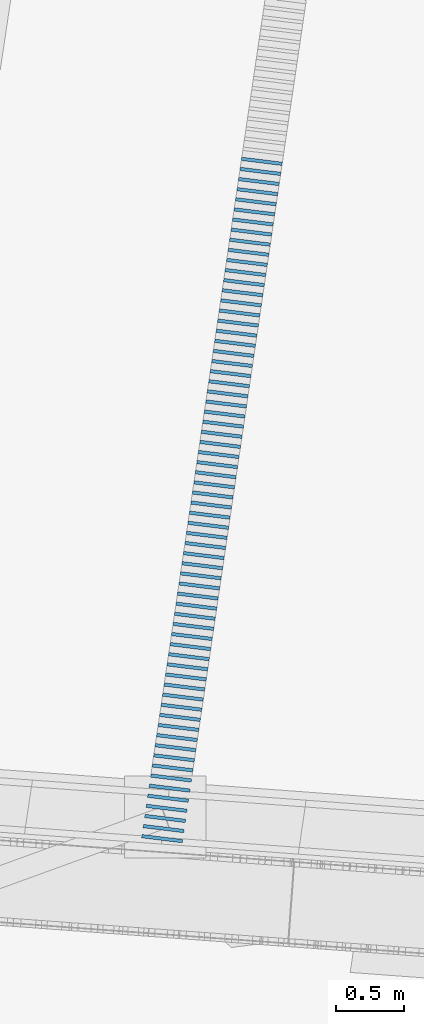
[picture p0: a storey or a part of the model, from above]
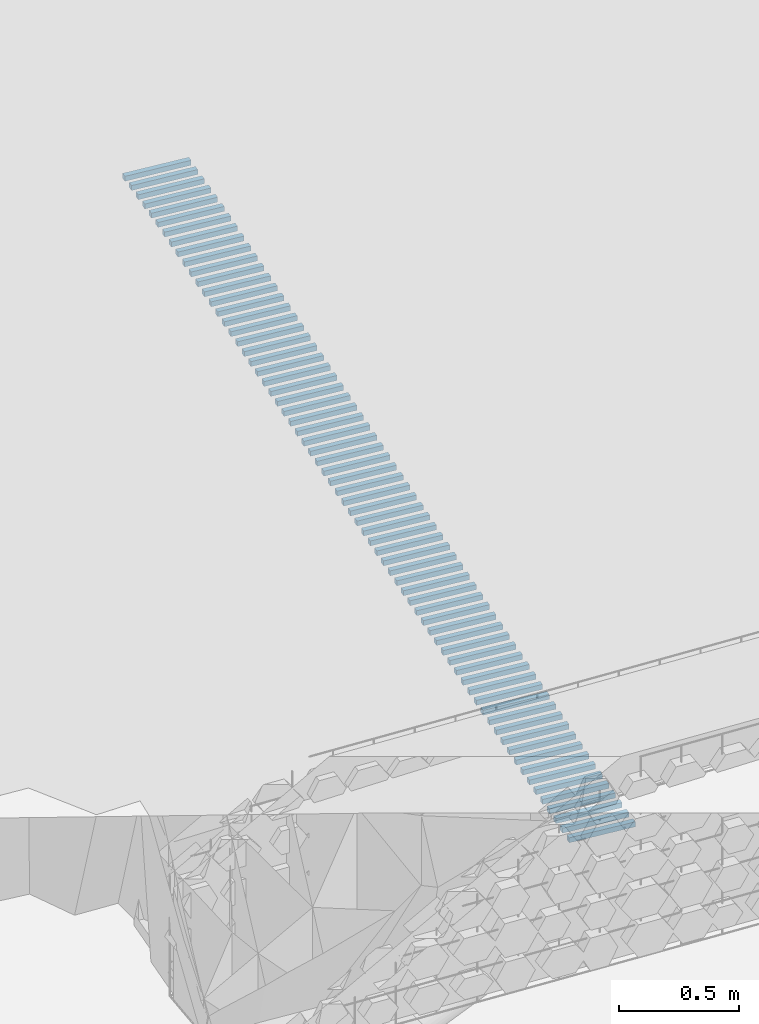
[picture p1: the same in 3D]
Properties of the parts of a building model (IFC4), part 1 of 3

# File
Description: ViewDefinition [CoordinationView]
File name: Casa_Sobreposta_Implantada.ifc
Time: 2026-10-02T12:27:42
Written by: IfcOpenShell 0.8.0
Made in: IfcOpenShell 0.8.0

# IfcProject, Casa Sobreposta · Lares · R06
Pset_CasaModel - Design: R06 single-storey exposed timber tiled roof, no attic floor; ReferenceFile: 260617_CasaDFL_Estrutura_Terreno.ifc; ModelStatus: DESIGN_STUDY; North: Survey grid +Y; Ramp: No upper floor or pedestrian ramp; EngineeringStatus: Member sizes, foundations, connections, bracing and environmental performance not verified; GroundFFL_m: 13.9; AreaLimit_m2: 250; CountedGeometricArea_m2: 163.712; GreenhouseExcludedByUser: no

# IfcSite, Lares · Rua das Mercês · artigo 4771
Pset_SurveySource - File: GN_09.26_213 Lares.dwg; SHA256: 0bca0a0751148bad1398f92d81b795428f94a57fea5e37dec0e125cea70402a1; Area_m2: 1636.5; BoundaryHandle: 31B; CoordinateReference: PT-TM06 / ETRS89; TerrainStatus: Proposed grading; original survey in separate IFC

# IfcBuilding, Casa Sobreposta
Pset_CasaPlacement - GroundFloorSurveyLevel_m: 13.9; UpperFloor: no; MoveEast_m: 3; MoveSouth_m: 0.5; RotationFromGridEast_deg: -8.5; BoundarySetbackRequired_m: 3; RuleBasis: User project constraint

# IfcBuildingStorey (2)
In: Casa Sobreposta
Name | Elevation (m)
00 · Habitação e estacionamento | 13.9
-01 · Cisterna sob o terraço | 11.3

# IfcSpace (11)
In: 00 · Habitação e estacionamento
Pset_CasaProvenance - DesignSource: Casa Sobreposta / configuration.json; ReferenceFile: 260617_CasaDFL_Estrutura_Terreno.ifc; ConstructionBasis: DESIGN_ASSUMPTION; Note: Functional zone from configurator; overlaps with partition footprints removed on ground floor. Not certified usable floor area.
Name | PredefinedType | NetFloorArea (m2)
Sala | INTERNAL | 31.359
Cozinha | INTERNAL | 9.94248
Banho | INTERNAL | 7.19804
WC | INTERNAL | 1.231
Serviço | INTERNAL | 4.16058
Acesso IS | INTERNAL | 3.99017
Quarto 1 | INTERNAL | 13.1145
Quarto 2 | INTERNAL | 13.1145
Quarto / escritório | INTERNAL | 37.8909
Circulação | INTERNAL | 18.1139
Estacionamento · 2 lugares | EXTERNAL | 32.55

# IfcAnnotation (4)
Pset_CasaProvenance - DesignSource: Casa Sobreposta / configuration.json; ReferenceFile: 260617_CasaDFL_Estrutura_Terreno.ifc; ConstructionBasis: DESIGN_ASSUMPTION
Name | In
Lugar P1 · 2.50 x 5.00 m | 00 · Habitação e estacionamento
Lugar P2 · 2.50 x 5.00 m | 00 · Habitação e estacionamento
Limite levantado · 31B | Lares · Rua das Mercês · artigo 4771
Afastamento de implantação · 3 m | Lares · Rua das Mercês · artigo 4771

# IfcBeam: TIMBER0.140x0.220 / timber (5)
In: 00 · Habitação e estacionamento
Type - Material: Madeira / Bauholz
Pset_CasaProvenance - DesignSource: Casa Sobreposta / configuration.json; ReferenceFile: 260617_CasaDFL_Estrutura_Terreno.ifc; ConstructionBasis: DESIGN_ASSUMPTION; Note: Visible timber concept; strength class, deflection, stability, wind and fire design pending.

# IfcBeam: TIMBER0.160x0.220 / timber (2)
In: 00 · Habitação e estacionamento
Type - Material: Madeira / Bauholz
Pset_CasaProvenance - DesignSource: Casa Sobreposta / configuration.json; ReferenceFile: 260617_CasaDFL_Estrutura_Terreno.ifc; ConstructionBasis: DESIGN_ASSUMPTION; Note: Visible timber concept; strength class, deflection, stability, wind and fire design pending.

# IfcBeam: TIMBER0.160x0.240 / timber (11)
In: 00 · Habitação e estacionamento
Type - Material: Madeira / Bauholz
Pset_CasaProvenance - DesignSource: Casa Sobreposta / configuration.json; ReferenceFile: 260617_CasaDFL_Estrutura_Terreno.ifc; ConstructionBasis: DESIGN_ASSUMPTION; Note: Visible timber concept; strength class, deflection, stability, wind and fire design pending.
Name
9 x Tesoura · tirante inferior
2 x Pérgola · viga

# IfcBuildingElementProxy: Acesso · caixa de retenção de sedimentos (2)
In: Lares · Rua das Mercês · artigo 4771
PredefinedType: USERDEFINED; Material: Caleiras · betão
Pset_CasaProvenance - DesignSource: Casa Sobreposta / configuration.json; ReferenceFile: 260617_CasaDFL_Estrutura_Terreno.ifc; ConstructionBasis: DESIGN_ASSUMPTION

# IfcBuildingElementProxy: Acesso · canal lateral (222)
In: Lares · Rua das Mercês · artigo 4771
PredefinedType: USERDEFINED; Material: Caleiras · betão
Pset_CasaProvenance - DesignSource: Casa Sobreposta / configuration.json; ReferenceFile: 260617_CasaDFL_Estrutura_Terreno.ifc; ConstructionBasis: DESIGN_ASSUMPTION; Note: R06 concept geometry; dimensions and connections not structurally verified.

# IfcBuildingElementProxy: Acesso · gabião -1 0.0 · cesto galvanizado
In: Lares · Rua das Mercês · artigo 4771
PredefinedType: USERDEFINED; Material: Aço galvanizado / Stahl verzinkt
Pset_CasaProvenance - DesignSource: Casa Sobreposta / configuration.json; ReferenceFile: 260617_CasaDFL_Estrutura_Terreno.ifc; ConstructionBasis: DESIGN_ASSUMPTION; Note: R06 concept geometry; dimensions and connections not structurally verified.

# IfcBuildingElementProxy: Acesso · gabião -1 0.0 · pedra aparente
In: Lares · Rua das Mercês · artigo 4771
PredefinedType: USERDEFINED; Material: Gabião · pedra irregular
Pset_CasaProvenance - DesignSource: Casa Sobreposta / configuration.json; ReferenceFile: 260617_CasaDFL_Estrutura_Terreno.ifc; ConstructionBasis: DESIGN_ASSUMPTION; Note: R06 concept geometry; dimensions and connections not structurally verified.

# IfcBuildingElementProxy: Acesso · gabião -1 12.0 · cesto galvanizado
In: Lares · Rua das Mercês · artigo 4771
PredefinedType: USERDEFINED; Material: Aço galvanizado / Stahl verzinkt
Pset_CasaProvenance - DesignSource: Casa Sobreposta / configuration.json; ReferenceFile: 260617_CasaDFL_Estrutura_Terreno.ifc; ConstructionBasis: DESIGN_ASSUMPTION; Note: R06 concept geometry; dimensions and connections not structurally verified.

# IfcBuildingElementProxy: Acesso · gabião -1 12.0 · pedra aparente
In: Lares · Rua das Mercês · artigo 4771
PredefinedType: USERDEFINED; Material: Gabião · pedra irregular
Pset_CasaProvenance - DesignSource: Casa Sobreposta / configuration.json; ReferenceFile: 260617_CasaDFL_Estrutura_Terreno.ifc; ConstructionBasis: DESIGN_ASSUMPTION; Note: R06 concept geometry; dimensions and connections not structurally verified.

# IfcBuildingElementProxy: Acesso · gabião -1 15.0 · cesto galvanizado
In: Lares · Rua das Mercês · artigo 4771
PredefinedType: USERDEFINED; Material: Aço galvanizado / Stahl verzinkt
Pset_CasaProvenance - DesignSource: Casa Sobreposta / configuration.json; ReferenceFile: 260617_CasaDFL_Estrutura_Terreno.ifc; ConstructionBasis: DESIGN_ASSUMPTION; Note: R06 concept geometry; dimensions and connections not structurally verified.

# IfcBuildingElementProxy: Acesso · gabião -1 15.0 · pedra aparente
In: Lares · Rua das Mercês · artigo 4771
PredefinedType: USERDEFINED; Material: Gabião · pedra irregular
Pset_CasaProvenance - DesignSource: Casa Sobreposta / configuration.json; ReferenceFile: 260617_CasaDFL_Estrutura_Terreno.ifc; ConstructionBasis: DESIGN_ASSUMPTION; Note: R06 concept geometry; dimensions and connections not structurally verified.

# IfcBuildingElementProxy: Acesso · gabião -1 18.0 · cesto galvanizado
In: Lares · Rua das Mercês · artigo 4771
PredefinedType: USERDEFINED; Material: Aço galvanizado / Stahl verzinkt
Pset_CasaProvenance - DesignSource: Casa Sobreposta / configuration.json; ReferenceFile: 260617_CasaDFL_Estrutura_Terreno.ifc; ConstructionBasis: DESIGN_ASSUMPTION; Note: R06 concept geometry; dimensions and connections not structurally verified.

# IfcBuildingElementProxy: Acesso · gabião -1 18.0 · pedra aparente
In: Lares · Rua das Mercês · artigo 4771
PredefinedType: USERDEFINED; Material: Gabião · pedra irregular
Pset_CasaProvenance - DesignSource: Casa Sobreposta / configuration.json; ReferenceFile: 260617_CasaDFL_Estrutura_Terreno.ifc; ConstructionBasis: DESIGN_ASSUMPTION; Note: R06 concept geometry; dimensions and connections not structurally verified.

# IfcBuildingElementProxy: Acesso · gabião -1 21.0 · cesto galvanizado
In: Lares · Rua das Mercês · artigo 4771
PredefinedType: USERDEFINED; Material: Aço galvanizado / Stahl verzinkt
Pset_CasaProvenance - DesignSource: Casa Sobreposta / configuration.json; ReferenceFile: 260617_CasaDFL_Estrutura_Terreno.ifc; ConstructionBasis: DESIGN_ASSUMPTION; Note: R06 concept geometry; dimensions and connections not structurally verified.

# IfcBuildingElementProxy: Acesso · gabião -1 21.0 · pedra aparente
In: Lares · Rua das Mercês · artigo 4771
PredefinedType: USERDEFINED; Material: Gabião · pedra irregular
Pset_CasaProvenance - DesignSource: Casa Sobreposta / configuration.json; ReferenceFile: 260617_CasaDFL_Estrutura_Terreno.ifc; ConstructionBasis: DESIGN_ASSUMPTION; Note: R06 concept geometry; dimensions and connections not structurally verified.

# IfcBuildingElementProxy: Acesso · gabião -1 24.0 · cesto galvanizado
In: Lares · Rua das Mercês · artigo 4771
PredefinedType: USERDEFINED; Material: Aço galvanizado / Stahl verzinkt
Pset_CasaProvenance - DesignSource: Casa Sobreposta / configuration.json; ReferenceFile: 260617_CasaDFL_Estrutura_Terreno.ifc; ConstructionBasis: DESIGN_ASSUMPTION; Note: R06 concept geometry; dimensions and connections not structurally verified.

# IfcBuildingElementProxy: Acesso · gabião -1 24.0 · pedra aparente
In: Lares · Rua das Mercês · artigo 4771
PredefinedType: USERDEFINED; Material: Gabião · pedra irregular
Pset_CasaProvenance - DesignSource: Casa Sobreposta / configuration.json; ReferenceFile: 260617_CasaDFL_Estrutura_Terreno.ifc; ConstructionBasis: DESIGN_ASSUMPTION; Note: R06 concept geometry; dimensions and connections not structurally verified.

# IfcBuildingElementProxy: Acesso · gabião -1 27.0 · cesto galvanizado
In: Lares · Rua das Mercês · artigo 4771
PredefinedType: USERDEFINED; Material: Aço galvanizado / Stahl verzinkt
Pset_CasaProvenance - DesignSource: Casa Sobreposta / configuration.json; ReferenceFile: 260617_CasaDFL_Estrutura_Terreno.ifc; ConstructionBasis: DESIGN_ASSUMPTION; Note: R06 concept geometry; dimensions and connections not structurally verified.

# IfcBuildingElementProxy: Acesso · gabião -1 27.0 · pedra aparente
In: Lares · Rua das Mercês · artigo 4771
PredefinedType: USERDEFINED; Material: Gabião · pedra irregular
Pset_CasaProvenance - DesignSource: Casa Sobreposta / configuration.json; ReferenceFile: 260617_CasaDFL_Estrutura_Terreno.ifc; ConstructionBasis: DESIGN_ASSUMPTION; Note: R06 concept geometry; dimensions and connections not structurally verified.

# IfcBuildingElementProxy: Acesso · gabião -1 3.0 · cesto galvanizado
In: Lares · Rua das Mercês · artigo 4771
PredefinedType: USERDEFINED; Material: Aço galvanizado / Stahl verzinkt
Pset_CasaProvenance - DesignSource: Casa Sobreposta / configuration.json; ReferenceFile: 260617_CasaDFL_Estrutura_Terreno.ifc; ConstructionBasis: DESIGN_ASSUMPTION; Note: R06 concept geometry; dimensions and connections not structurally verified.

# IfcBuildingElementProxy: Acesso · gabião -1 3.0 · pedra aparente
In: Lares · Rua das Mercês · artigo 4771
PredefinedType: USERDEFINED; Material: Gabião · pedra irregular
Pset_CasaProvenance - DesignSource: Casa Sobreposta / configuration.json; ReferenceFile: 260617_CasaDFL_Estrutura_Terreno.ifc; ConstructionBasis: DESIGN_ASSUMPTION; Note: R06 concept geometry; dimensions and connections not structurally verified.

# IfcBuildingElementProxy: Acesso · gabião -1 30.0 · cesto galvanizado
In: Lares · Rua das Mercês · artigo 4771
PredefinedType: USERDEFINED; Material: Aço galvanizado / Stahl verzinkt
Pset_CasaProvenance - DesignSource: Casa Sobreposta / configuration.json; ReferenceFile: 260617_CasaDFL_Estrutura_Terreno.ifc; ConstructionBasis: DESIGN_ASSUMPTION; Note: R06 concept geometry; dimensions and connections not structurally verified.

# IfcBuildingElementProxy: Acesso · gabião -1 30.0 · pedra aparente
In: Lares · Rua das Mercês · artigo 4771
PredefinedType: USERDEFINED; Material: Gabião · pedra irregular
Pset_CasaProvenance - DesignSource: Casa Sobreposta / configuration.json; ReferenceFile: 260617_CasaDFL_Estrutura_Terreno.ifc; ConstructionBasis: DESIGN_ASSUMPTION; Note: R06 concept geometry; dimensions and connections not structurally verified.

# IfcBuildingElementProxy: Acesso · gabião -1 33.0 · cesto galvanizado
In: Lares · Rua das Mercês · artigo 4771
PredefinedType: USERDEFINED; Material: Aço galvanizado / Stahl verzinkt
Pset_CasaProvenance - DesignSource: Casa Sobreposta / configuration.json; ReferenceFile: 260617_CasaDFL_Estrutura_Terreno.ifc; ConstructionBasis: DESIGN_ASSUMPTION; Note: R06 concept geometry; dimensions and connections not structurally verified.

# IfcBuildingElementProxy: Acesso · gabião -1 33.0 · pedra aparente
In: Lares · Rua das Mercês · artigo 4771
PredefinedType: USERDEFINED; Material: Gabião · pedra irregular
Pset_CasaProvenance - DesignSource: Casa Sobreposta / configuration.json; ReferenceFile: 260617_CasaDFL_Estrutura_Terreno.ifc; ConstructionBasis: DESIGN_ASSUMPTION; Note: R06 concept geometry; dimensions and connections not structurally verified.

# IfcBuildingElementProxy: Acesso · gabião -1 6.0 · cesto galvanizado
In: Lares · Rua das Mercês · artigo 4771
PredefinedType: USERDEFINED; Material: Aço galvanizado / Stahl verzinkt
Pset_CasaProvenance - DesignSource: Casa Sobreposta / configuration.json; ReferenceFile: 260617_CasaDFL_Estrutura_Terreno.ifc; ConstructionBasis: DESIGN_ASSUMPTION; Note: R06 concept geometry; dimensions and connections not structurally verified.

# IfcBuildingElementProxy: Acesso · gabião -1 6.0 · pedra aparente
In: Lares · Rua das Mercês · artigo 4771
PredefinedType: USERDEFINED; Material: Gabião · pedra irregular
Pset_CasaProvenance - DesignSource: Casa Sobreposta / configuration.json; ReferenceFile: 260617_CasaDFL_Estrutura_Terreno.ifc; ConstructionBasis: DESIGN_ASSUMPTION; Note: R06 concept geometry; dimensions and connections not structurally verified.

# IfcBuildingElementProxy: Acesso · gabião -1 9.0 · cesto galvanizado
In: Lares · Rua das Mercês · artigo 4771
PredefinedType: USERDEFINED; Material: Aço galvanizado / Stahl verzinkt
Pset_CasaProvenance - DesignSource: Casa Sobreposta / configuration.json; ReferenceFile: 260617_CasaDFL_Estrutura_Terreno.ifc; ConstructionBasis: DESIGN_ASSUMPTION; Note: R06 concept geometry; dimensions and connections not structurally verified.

# IfcBuildingElementProxy: Acesso · gabião -1 9.0 · pedra aparente
In: Lares · Rua das Mercês · artigo 4771
PredefinedType: USERDEFINED; Material: Gabião · pedra irregular
Pset_CasaProvenance - DesignSource: Casa Sobreposta / configuration.json; ReferenceFile: 260617_CasaDFL_Estrutura_Terreno.ifc; ConstructionBasis: DESIGN_ASSUMPTION; Note: R06 concept geometry; dimensions and connections not structurally verified.

# IfcBuildingElementProxy: Acesso · gabião 1 0.0 · cesto galvanizado
In: Lares · Rua das Mercês · artigo 4771
PredefinedType: USERDEFINED; Material: Aço galvanizado / Stahl verzinkt
Pset_CasaProvenance - DesignSource: Casa Sobreposta / configuration.json; ReferenceFile: 260617_CasaDFL_Estrutura_Terreno.ifc; ConstructionBasis: DESIGN_ASSUMPTION; Note: R06 concept geometry; dimensions and connections not structurally verified.

# IfcBuildingElementProxy: Acesso · gabião 1 0.0 · pedra aparente
In: Lares · Rua das Mercês · artigo 4771
PredefinedType: USERDEFINED; Material: Gabião · pedra irregular
Pset_CasaProvenance - DesignSource: Casa Sobreposta / configuration.json; ReferenceFile: 260617_CasaDFL_Estrutura_Terreno.ifc; ConstructionBasis: DESIGN_ASSUMPTION; Note: R06 concept geometry; dimensions and connections not structurally verified.

# IfcBuildingElementProxy: Acesso · gabião 1 12.0 · cesto galvanizado
In: Lares · Rua das Mercês · artigo 4771
PredefinedType: USERDEFINED; Material: Aço galvanizado / Stahl verzinkt
Pset_CasaProvenance - DesignSource: Casa Sobreposta / configuration.json; ReferenceFile: 260617_CasaDFL_Estrutura_Terreno.ifc; ConstructionBasis: DESIGN_ASSUMPTION; Note: R06 concept geometry; dimensions and connections not structurally verified.

# IfcBuildingElementProxy: Acesso · gabião 1 12.0 · pedra aparente
In: Lares · Rua das Mercês · artigo 4771
PredefinedType: USERDEFINED; Material: Gabião · pedra irregular
Pset_CasaProvenance - DesignSource: Casa Sobreposta / configuration.json; ReferenceFile: 260617_CasaDFL_Estrutura_Terreno.ifc; ConstructionBasis: DESIGN_ASSUMPTION; Note: R06 concept geometry; dimensions and connections not structurally verified.

# IfcBuildingElementProxy: Acesso · gabião 1 15.0 · cesto galvanizado
In: Lares · Rua das Mercês · artigo 4771
PredefinedType: USERDEFINED; Material: Aço galvanizado / Stahl verzinkt
Pset_CasaProvenance - DesignSource: Casa Sobreposta / configuration.json; ReferenceFile: 260617_CasaDFL_Estrutura_Terreno.ifc; ConstructionBasis: DESIGN_ASSUMPTION; Note: R06 concept geometry; dimensions and connections not structurally verified.

# IfcBuildingElementProxy: Acesso · gabião 1 15.0 · pedra aparente
In: Lares · Rua das Mercês · artigo 4771
PredefinedType: USERDEFINED; Material: Gabião · pedra irregular
Pset_CasaProvenance - DesignSource: Casa Sobreposta / configuration.json; ReferenceFile: 260617_CasaDFL_Estrutura_Terreno.ifc; ConstructionBasis: DESIGN_ASSUMPTION; Note: R06 concept geometry; dimensions and connections not structurally verified.

# IfcBuildingElementProxy: Acesso · gabião 1 18.0 · cesto galvanizado
In: Lares · Rua das Mercês · artigo 4771
PredefinedType: USERDEFINED; Material: Aço galvanizado / Stahl verzinkt
Pset_CasaProvenance - DesignSource: Casa Sobreposta / configuration.json; ReferenceFile: 260617_CasaDFL_Estrutura_Terreno.ifc; ConstructionBasis: DESIGN_ASSUMPTION; Note: R06 concept geometry; dimensions and connections not structurally verified.

# IfcBuildingElementProxy: Acesso · gabião 1 18.0 · pedra aparente
In: Lares · Rua das Mercês · artigo 4771
PredefinedType: USERDEFINED; Material: Gabião · pedra irregular
Pset_CasaProvenance - DesignSource: Casa Sobreposta / configuration.json; ReferenceFile: 260617_CasaDFL_Estrutura_Terreno.ifc; ConstructionBasis: DESIGN_ASSUMPTION; Note: R06 concept geometry; dimensions and connections not structurally verified.

# IfcBuildingElementProxy: Acesso · gabião 1 21.0 · cesto galvanizado
In: Lares · Rua das Mercês · artigo 4771
PredefinedType: USERDEFINED; Material: Aço galvanizado / Stahl verzinkt
Pset_CasaProvenance - DesignSource: Casa Sobreposta / configuration.json; ReferenceFile: 260617_CasaDFL_Estrutura_Terreno.ifc; ConstructionBasis: DESIGN_ASSUMPTION; Note: R06 concept geometry; dimensions and connections not structurally verified.

# IfcBuildingElementProxy: Acesso · gabião 1 21.0 · pedra aparente
In: Lares · Rua das Mercês · artigo 4771
PredefinedType: USERDEFINED; Material: Gabião · pedra irregular
Pset_CasaProvenance - DesignSource: Casa Sobreposta / configuration.json; ReferenceFile: 260617_CasaDFL_Estrutura_Terreno.ifc; ConstructionBasis: DESIGN_ASSUMPTION; Note: R06 concept geometry; dimensions and connections not structurally verified.

# IfcBuildingElementProxy: Acesso · gabião 1 24.0 · cesto galvanizado
In: Lares · Rua das Mercês · artigo 4771
PredefinedType: USERDEFINED; Material: Aço galvanizado / Stahl verzinkt
Pset_CasaProvenance - DesignSource: Casa Sobreposta / configuration.json; ReferenceFile: 260617_CasaDFL_Estrutura_Terreno.ifc; ConstructionBasis: DESIGN_ASSUMPTION; Note: R06 concept geometry; dimensions and connections not structurally verified.

# IfcBuildingElementProxy: Acesso · gabião 1 24.0 · pedra aparente
In: Lares · Rua das Mercês · artigo 4771
PredefinedType: USERDEFINED; Material: Gabião · pedra irregular
Pset_CasaProvenance - DesignSource: Casa Sobreposta / configuration.json; ReferenceFile: 260617_CasaDFL_Estrutura_Terreno.ifc; ConstructionBasis: DESIGN_ASSUMPTION; Note: R06 concept geometry; dimensions and connections not structurally verified.

# IfcBuildingElementProxy: Acesso · gabião 1 27.0 · cesto galvanizado
In: Lares · Rua das Mercês · artigo 4771
PredefinedType: USERDEFINED; Material: Aço galvanizado / Stahl verzinkt
Pset_CasaProvenance - DesignSource: Casa Sobreposta / configuration.json; ReferenceFile: 260617_CasaDFL_Estrutura_Terreno.ifc; ConstructionBasis: DESIGN_ASSUMPTION; Note: R06 concept geometry; dimensions and connections not structurally verified.

# IfcBuildingElementProxy: Acesso · gabião 1 27.0 · pedra aparente
In: Lares · Rua das Mercês · artigo 4771
PredefinedType: USERDEFINED; Material: Gabião · pedra irregular
Pset_CasaProvenance - DesignSource: Casa Sobreposta / configuration.json; ReferenceFile: 260617_CasaDFL_Estrutura_Terreno.ifc; ConstructionBasis: DESIGN_ASSUMPTION; Note: R06 concept geometry; dimensions and connections not structurally verified.

# IfcBuildingElementProxy: Acesso · gabião 1 3.0 · cesto galvanizado
In: Lares · Rua das Mercês · artigo 4771
PredefinedType: USERDEFINED; Material: Aço galvanizado / Stahl verzinkt
Pset_CasaProvenance - DesignSource: Casa Sobreposta / configuration.json; ReferenceFile: 260617_CasaDFL_Estrutura_Terreno.ifc; ConstructionBasis: DESIGN_ASSUMPTION; Note: R06 concept geometry; dimensions and connections not structurally verified.

# IfcBuildingElementProxy: Acesso · gabião 1 3.0 · pedra aparente
In: Lares · Rua das Mercês · artigo 4771
PredefinedType: USERDEFINED; Material: Gabião · pedra irregular
Pset_CasaProvenance - DesignSource: Casa Sobreposta / configuration.json; ReferenceFile: 260617_CasaDFL_Estrutura_Terreno.ifc; ConstructionBasis: DESIGN_ASSUMPTION; Note: R06 concept geometry; dimensions and connections not structurally verified.

# IfcBuildingElementProxy: Acesso · gabião 1 30.0 · cesto galvanizado
In: Lares · Rua das Mercês · artigo 4771
PredefinedType: USERDEFINED; Material: Aço galvanizado / Stahl verzinkt
Pset_CasaProvenance - DesignSource: Casa Sobreposta / configuration.json; ReferenceFile: 260617_CasaDFL_Estrutura_Terreno.ifc; ConstructionBasis: DESIGN_ASSUMPTION; Note: R06 concept geometry; dimensions and connections not structurally verified.

# IfcBuildingElementProxy: Acesso · gabião 1 30.0 · pedra aparente
In: Lares · Rua das Mercês · artigo 4771
PredefinedType: USERDEFINED; Material: Gabião · pedra irregular
Pset_CasaProvenance - DesignSource: Casa Sobreposta / configuration.json; ReferenceFile: 260617_CasaDFL_Estrutura_Terreno.ifc; ConstructionBasis: DESIGN_ASSUMPTION; Note: R06 concept geometry; dimensions and connections not structurally verified.

# IfcBuildingElementProxy: Acesso · gabião 1 33.0 · cesto galvanizado
In: Lares · Rua das Mercês · artigo 4771
PredefinedType: USERDEFINED; Material: Aço galvanizado / Stahl verzinkt
Pset_CasaProvenance - DesignSource: Casa Sobreposta / configuration.json; ReferenceFile: 260617_CasaDFL_Estrutura_Terreno.ifc; ConstructionBasis: DESIGN_ASSUMPTION; Note: R06 concept geometry; dimensions and connections not structurally verified.

# IfcBuildingElementProxy: Acesso · gabião 1 33.0 · pedra aparente
In: Lares · Rua das Mercês · artigo 4771
PredefinedType: USERDEFINED; Material: Gabião · pedra irregular
Pset_CasaProvenance - DesignSource: Casa Sobreposta / configuration.json; ReferenceFile: 260617_CasaDFL_Estrutura_Terreno.ifc; ConstructionBasis: DESIGN_ASSUMPTION; Note: R06 concept geometry; dimensions and connections not structurally verified.

# IfcBuildingElementProxy: Acesso · gabião 1 6.0 · cesto galvanizado
In: Lares · Rua das Mercês · artigo 4771
PredefinedType: USERDEFINED; Material: Aço galvanizado / Stahl verzinkt
Pset_CasaProvenance - DesignSource: Casa Sobreposta / configuration.json; ReferenceFile: 260617_CasaDFL_Estrutura_Terreno.ifc; ConstructionBasis: DESIGN_ASSUMPTION; Note: R06 concept geometry; dimensions and connections not structurally verified.

# IfcBuildingElementProxy: Acesso · gabião 1 6.0 · pedra aparente
In: Lares · Rua das Mercês · artigo 4771
PredefinedType: USERDEFINED; Material: Gabião · pedra irregular
Pset_CasaProvenance - DesignSource: Casa Sobreposta / configuration.json; ReferenceFile: 260617_CasaDFL_Estrutura_Terreno.ifc; ConstructionBasis: DESIGN_ASSUMPTION; Note: R06 concept geometry; dimensions and connections not structurally verified.

# IfcBuildingElementProxy: Acesso · gabião 1 9.0 · cesto galvanizado
In: Lares · Rua das Mercês · artigo 4771
PredefinedType: USERDEFINED; Material: Aço galvanizado / Stahl verzinkt
Pset_CasaProvenance - DesignSource: Casa Sobreposta / configuration.json; ReferenceFile: 260617_CasaDFL_Estrutura_Terreno.ifc; ConstructionBasis: DESIGN_ASSUMPTION; Note: R06 concept geometry; dimensions and connections not structurally verified.

# IfcBuildingElementProxy: Acesso · gabião 1 9.0 · pedra aparente
In: Lares · Rua das Mercês · artigo 4771
PredefinedType: USERDEFINED; Material: Gabião · pedra irregular
Pset_CasaProvenance - DesignSource: Casa Sobreposta / configuration.json; ReferenceFile: 260617_CasaDFL_Estrutura_Terreno.ifc; ConstructionBasis: DESIGN_ASSUMPTION; Note: R06 concept geometry; dimensions and connections not structurally verified.

# IfcBuildingElementProxy: Cisterna · água a 2,00 m, hipótese
In: -01 · Cisterna sob o terraço
PredefinedType: USERDEFINED; Material: Água pluvial · nível ilustrativo
Pset_CasaProvenance - DesignSource: Casa Sobreposta / configuration.json; ReferenceFile: 260617_CasaDFL_Estrutura_Terreno.ifc; ConstructionBasis: DESIGN_ASSUMPTION; Note: Illustrative water envelope, not concrete or a certified operating capacity.

# IfcBuildingElementProxy: Cobertura · caleira pluvial para cisterna (2)
In: 00 · Habitação e estacionamento
PredefinedType: USERDEFINED; Material: Aço galvanizado / Stahl verzinkt
Pset_CasaProvenance - DesignSource: Casa Sobreposta / configuration.json; ReferenceFile: 260617_CasaDFL_Estrutura_Terreno.ifc; ConstructionBasis: DESIGN_ASSUMPTION

# IfcBuildingElementProxy: Interceção · caleira estacionamento
In: Lares · Rua das Mercês · artigo 4771
PredefinedType: USERDEFINED; Material: Caleiras · betão
Pset_CasaProvenance - DesignSource: Casa Sobreposta / configuration.json; ReferenceFile: 260617_CasaDFL_Estrutura_Terreno.ifc; ConstructionBasis: DESIGN_ASSUMPTION

# IfcBuildingElementProxy: Interceção · caleira rua
In: Lares · Rua das Mercês · artigo 4771
PredefinedType: USERDEFINED; Material: Caleiras · betão
Pset_CasaProvenance - DesignSource: Casa Sobreposta / configuration.json; ReferenceFile: 260617_CasaDFL_Estrutura_Terreno.ifc; ConstructionBasis: DESIGN_ASSUMPTION

# IfcBuildingElementProxy: Limite north · gabião 10 · cesto galvanizado
In: Lares · Rua das Mercês · artigo 4771
PredefinedType: USERDEFINED; Material: Aço galvanizado / Stahl verzinkt
Pset_CasaProvenance - DesignSource: Casa Sobreposta / configuration.json; ReferenceFile: 260617_CasaDFL_Estrutura_Terreno.ifc; ConstructionBasis: DESIGN_ASSUMPTION; Note: R06 concept geometry; dimensions and connections not structurally verified.

# IfcBuildingElementProxy: Limite north · gabião 10 · pedra aparente
In: Lares · Rua das Mercês · artigo 4771
PredefinedType: USERDEFINED; Material: Gabião · pedra irregular
Pset_CasaProvenance - DesignSource: Casa Sobreposta / configuration.json; ReferenceFile: 260617_CasaDFL_Estrutura_Terreno.ifc; ConstructionBasis: DESIGN_ASSUMPTION; Note: R06 concept geometry; dimensions and connections not structurally verified.

# IfcBuildingElementProxy: Limite north · gabião 11 · cesto galvanizado
In: Lares · Rua das Mercês · artigo 4771
PredefinedType: USERDEFINED; Material: Aço galvanizado / Stahl verzinkt
Pset_CasaProvenance - DesignSource: Casa Sobreposta / configuration.json; ReferenceFile: 260617_CasaDFL_Estrutura_Terreno.ifc; ConstructionBasis: DESIGN_ASSUMPTION; Note: R06 concept geometry; dimensions and connections not structurally verified.

# IfcBuildingElementProxy: Limite north · gabião 11 · pedra aparente
In: Lares · Rua das Mercês · artigo 4771
PredefinedType: USERDEFINED; Material: Gabião · pedra irregular
Pset_CasaProvenance - DesignSource: Casa Sobreposta / configuration.json; ReferenceFile: 260617_CasaDFL_Estrutura_Terreno.ifc; ConstructionBasis: DESIGN_ASSUMPTION; Note: R06 concept geometry; dimensions and connections not structurally verified.

# IfcBuildingElementProxy: Limite north · gabião 12 · cesto galvanizado
In: Lares · Rua das Mercês · artigo 4771
PredefinedType: USERDEFINED; Material: Aço galvanizado / Stahl verzinkt
Pset_CasaProvenance - DesignSource: Casa Sobreposta / configuration.json; ReferenceFile: 260617_CasaDFL_Estrutura_Terreno.ifc; ConstructionBasis: DESIGN_ASSUMPTION; Note: R06 concept geometry; dimensions and connections not structurally verified.

# IfcBuildingElementProxy: Limite north · gabião 12 · pedra aparente
In: Lares · Rua das Mercês · artigo 4771
PredefinedType: USERDEFINED; Material: Gabião · pedra irregular
Pset_CasaProvenance - DesignSource: Casa Sobreposta / configuration.json; ReferenceFile: 260617_CasaDFL_Estrutura_Terreno.ifc; ConstructionBasis: DESIGN_ASSUMPTION; Note: R06 concept geometry; dimensions and connections not structurally verified.

# IfcBuildingElementProxy: Limite north · gabião 13 · cesto galvanizado
In: Lares · Rua das Mercês · artigo 4771
PredefinedType: USERDEFINED; Material: Aço galvanizado / Stahl verzinkt
Pset_CasaProvenance - DesignSource: Casa Sobreposta / configuration.json; ReferenceFile: 260617_CasaDFL_Estrutura_Terreno.ifc; ConstructionBasis: DESIGN_ASSUMPTION; Note: R06 concept geometry; dimensions and connections not structurally verified.

# IfcBuildingElementProxy: Limite north · gabião 13 · pedra aparente
In: Lares · Rua das Mercês · artigo 4771
PredefinedType: USERDEFINED; Material: Gabião · pedra irregular
Pset_CasaProvenance - DesignSource: Casa Sobreposta / configuration.json; ReferenceFile: 260617_CasaDFL_Estrutura_Terreno.ifc; ConstructionBasis: DESIGN_ASSUMPTION; Note: R06 concept geometry; dimensions and connections not structurally verified.

# IfcBuildingElementProxy: Limite north · gabião 14 · cesto galvanizado
In: Lares · Rua das Mercês · artigo 4771
PredefinedType: USERDEFINED; Material: Aço galvanizado / Stahl verzinkt
Pset_CasaProvenance - DesignSource: Casa Sobreposta / configuration.json; ReferenceFile: 260617_CasaDFL_Estrutura_Terreno.ifc; ConstructionBasis: DESIGN_ASSUMPTION; Note: R06 concept geometry; dimensions and connections not structurally verified.

# IfcBuildingElementProxy: Limite north · gabião 14 · pedra aparente
In: Lares · Rua das Mercês · artigo 4771
PredefinedType: USERDEFINED; Material: Gabião · pedra irregular
Pset_CasaProvenance - DesignSource: Casa Sobreposta / configuration.json; ReferenceFile: 260617_CasaDFL_Estrutura_Terreno.ifc; ConstructionBasis: DESIGN_ASSUMPTION; Note: R06 concept geometry; dimensions and connections not structurally verified.

# IfcBuildingElementProxy: Limite north · gabião 15 · cesto galvanizado
In: Lares · Rua das Mercês · artigo 4771
PredefinedType: USERDEFINED; Material: Aço galvanizado / Stahl verzinkt
Pset_CasaProvenance - DesignSource: Casa Sobreposta / configuration.json; ReferenceFile: 260617_CasaDFL_Estrutura_Terreno.ifc; ConstructionBasis: DESIGN_ASSUMPTION; Note: R06 concept geometry; dimensions and connections not structurally verified.

# IfcBuildingElementProxy: Limite north · gabião 15 · pedra aparente
In: Lares · Rua das Mercês · artigo 4771
PredefinedType: USERDEFINED; Material: Gabião · pedra irregular
Pset_CasaProvenance - DesignSource: Casa Sobreposta / configuration.json; ReferenceFile: 260617_CasaDFL_Estrutura_Terreno.ifc; ConstructionBasis: DESIGN_ASSUMPTION; Note: R06 concept geometry; dimensions and connections not structurally verified.

# IfcBuildingElementProxy: Limite north · gabião 16 · cesto galvanizado
In: Lares · Rua das Mercês · artigo 4771
PredefinedType: USERDEFINED; Material: Aço galvanizado / Stahl verzinkt
Pset_CasaProvenance - DesignSource: Casa Sobreposta / configuration.json; ReferenceFile: 260617_CasaDFL_Estrutura_Terreno.ifc; ConstructionBasis: DESIGN_ASSUMPTION; Note: R06 concept geometry; dimensions and connections not structurally verified.

# IfcBuildingElementProxy: Limite north · gabião 16 · pedra aparente
In: Lares · Rua das Mercês · artigo 4771
PredefinedType: USERDEFINED; Material: Gabião · pedra irregular
Pset_CasaProvenance - DesignSource: Casa Sobreposta / configuration.json; ReferenceFile: 260617_CasaDFL_Estrutura_Terreno.ifc; ConstructionBasis: DESIGN_ASSUMPTION; Note: R06 concept geometry; dimensions and connections not structurally verified.

# IfcBuildingElementProxy: Limite north · gabião 17 · cesto galvanizado
In: Lares · Rua das Mercês · artigo 4771
PredefinedType: USERDEFINED; Material: Aço galvanizado / Stahl verzinkt
Pset_CasaProvenance - DesignSource: Casa Sobreposta / configuration.json; ReferenceFile: 260617_CasaDFL_Estrutura_Terreno.ifc; ConstructionBasis: DESIGN_ASSUMPTION; Note: R06 concept geometry; dimensions and connections not structurally verified.

# IfcBuildingElementProxy: Limite north · gabião 17 · pedra aparente
In: Lares · Rua das Mercês · artigo 4771
PredefinedType: USERDEFINED; Material: Gabião · pedra irregular
Pset_CasaProvenance - DesignSource: Casa Sobreposta / configuration.json; ReferenceFile: 260617_CasaDFL_Estrutura_Terreno.ifc; ConstructionBasis: DESIGN_ASSUMPTION; Note: R06 concept geometry; dimensions and connections not structurally verified.

# IfcBuildingElementProxy: Limite north · gabião 18 · cesto galvanizado
In: Lares · Rua das Mercês · artigo 4771
PredefinedType: USERDEFINED; Material: Aço galvanizado / Stahl verzinkt
Pset_CasaProvenance - DesignSource: Casa Sobreposta / configuration.json; ReferenceFile: 260617_CasaDFL_Estrutura_Terreno.ifc; ConstructionBasis: DESIGN_ASSUMPTION; Note: R06 concept geometry; dimensions and connections not structurally verified.

# IfcBuildingElementProxy: Limite north · gabião 18 · pedra aparente
In: Lares · Rua das Mercês · artigo 4771
PredefinedType: USERDEFINED; Material: Gabião · pedra irregular
Pset_CasaProvenance - DesignSource: Casa Sobreposta / configuration.json; ReferenceFile: 260617_CasaDFL_Estrutura_Terreno.ifc; ConstructionBasis: DESIGN_ASSUMPTION; Note: R06 concept geometry; dimensions and connections not structurally verified.

# IfcBuildingElementProxy: Limite north · gabião 19 · cesto galvanizado
In: Lares · Rua das Mercês · artigo 4771
PredefinedType: USERDEFINED; Material: Aço galvanizado / Stahl verzinkt
Pset_CasaProvenance - DesignSource: Casa Sobreposta / configuration.json; ReferenceFile: 260617_CasaDFL_Estrutura_Terreno.ifc; ConstructionBasis: DESIGN_ASSUMPTION; Note: R06 concept geometry; dimensions and connections not structurally verified.

# IfcBuildingElementProxy: Limite north · gabião 19 · pedra aparente
In: Lares · Rua das Mercês · artigo 4771
PredefinedType: USERDEFINED; Material: Gabião · pedra irregular
Pset_CasaProvenance - DesignSource: Casa Sobreposta / configuration.json; ReferenceFile: 260617_CasaDFL_Estrutura_Terreno.ifc; ConstructionBasis: DESIGN_ASSUMPTION; Note: R06 concept geometry; dimensions and connections not structurally verified.

# IfcBuildingElementProxy: Limite north · gabião 20 · cesto galvanizado
In: Lares · Rua das Mercês · artigo 4771
PredefinedType: USERDEFINED; Material: Aço galvanizado / Stahl verzinkt
Pset_CasaProvenance - DesignSource: Casa Sobreposta / configuration.json; ReferenceFile: 260617_CasaDFL_Estrutura_Terreno.ifc; ConstructionBasis: DESIGN_ASSUMPTION; Note: R06 concept geometry; dimensions and connections not structurally verified.

# IfcBuildingElementProxy: Limite north · gabião 20 · pedra aparente
In: Lares · Rua das Mercês · artigo 4771
PredefinedType: USERDEFINED; Material: Gabião · pedra irregular
Pset_CasaProvenance - DesignSource: Casa Sobreposta / configuration.json; ReferenceFile: 260617_CasaDFL_Estrutura_Terreno.ifc; ConstructionBasis: DESIGN_ASSUMPTION; Note: R06 concept geometry; dimensions and connections not structurally verified.

# IfcBuildingElementProxy: Limite north · gabião 21 · cesto galvanizado
In: Lares · Rua das Mercês · artigo 4771
PredefinedType: USERDEFINED; Material: Aço galvanizado / Stahl verzinkt
Pset_CasaProvenance - DesignSource: Casa Sobreposta / configuration.json; ReferenceFile: 260617_CasaDFL_Estrutura_Terreno.ifc; ConstructionBasis: DESIGN_ASSUMPTION; Note: R06 concept geometry; dimensions and connections not structurally verified.

# IfcBuildingElementProxy: Limite north · gabião 21 · pedra aparente
In: Lares · Rua das Mercês · artigo 4771
PredefinedType: USERDEFINED; Material: Gabião · pedra irregular
Pset_CasaProvenance - DesignSource: Casa Sobreposta / configuration.json; ReferenceFile: 260617_CasaDFL_Estrutura_Terreno.ifc; ConstructionBasis: DESIGN_ASSUMPTION; Note: R06 concept geometry; dimensions and connections not structurally verified.

# IfcBuildingElementProxy: Limite north · gabião 22 · cesto galvanizado
In: Lares · Rua das Mercês · artigo 4771
PredefinedType: USERDEFINED; Material: Aço galvanizado / Stahl verzinkt
Pset_CasaProvenance - DesignSource: Casa Sobreposta / configuration.json; ReferenceFile: 260617_CasaDFL_Estrutura_Terreno.ifc; ConstructionBasis: DESIGN_ASSUMPTION; Note: R06 concept geometry; dimensions and connections not structurally verified.

# IfcBuildingElementProxy: Limite north · gabião 22 · pedra aparente
In: Lares · Rua das Mercês · artigo 4771
PredefinedType: USERDEFINED; Material: Gabião · pedra irregular
Pset_CasaProvenance - DesignSource: Casa Sobreposta / configuration.json; ReferenceFile: 260617_CasaDFL_Estrutura_Terreno.ifc; ConstructionBasis: DESIGN_ASSUMPTION; Note: R06 concept geometry; dimensions and connections not structurally verified.

# IfcBuildingElementProxy: Limite north · gabião 23 · cesto galvanizado
In: Lares · Rua das Mercês · artigo 4771
PredefinedType: USERDEFINED; Material: Aço galvanizado / Stahl verzinkt
Pset_CasaProvenance - DesignSource: Casa Sobreposta / configuration.json; ReferenceFile: 260617_CasaDFL_Estrutura_Terreno.ifc; ConstructionBasis: DESIGN_ASSUMPTION; Note: R06 concept geometry; dimensions and connections not structurally verified.

# IfcBuildingElementProxy: Limite north · gabião 23 · pedra aparente
In: Lares · Rua das Mercês · artigo 4771
PredefinedType: USERDEFINED; Material: Gabião · pedra irregular
Pset_CasaProvenance - DesignSource: Casa Sobreposta / configuration.json; ReferenceFile: 260617_CasaDFL_Estrutura_Terreno.ifc; ConstructionBasis: DESIGN_ASSUMPTION; Note: R06 concept geometry; dimensions and connections not structurally verified.

# IfcBuildingElementProxy: Limite north · gabião 24 · cesto galvanizado
In: Lares · Rua das Mercês · artigo 4771
PredefinedType: USERDEFINED; Material: Aço galvanizado / Stahl verzinkt
Pset_CasaProvenance - DesignSource: Casa Sobreposta / configuration.json; ReferenceFile: 260617_CasaDFL_Estrutura_Terreno.ifc; ConstructionBasis: DESIGN_ASSUMPTION; Note: R06 concept geometry; dimensions and connections not structurally verified.

# IfcBuildingElementProxy: Limite north · gabião 24 · pedra aparente
In: Lares · Rua das Mercês · artigo 4771
PredefinedType: USERDEFINED; Material: Gabião · pedra irregular
Pset_CasaProvenance - DesignSource: Casa Sobreposta / configuration.json; ReferenceFile: 260617_CasaDFL_Estrutura_Terreno.ifc; ConstructionBasis: DESIGN_ASSUMPTION; Note: R06 concept geometry; dimensions and connections not structurally verified.

# IfcBuildingElementProxy: Limite north · gabião 25 · cesto galvanizado
In: Lares · Rua das Mercês · artigo 4771
PredefinedType: USERDEFINED; Material: Aço galvanizado / Stahl verzinkt
Pset_CasaProvenance - DesignSource: Casa Sobreposta / configuration.json; ReferenceFile: 260617_CasaDFL_Estrutura_Terreno.ifc; ConstructionBasis: DESIGN_ASSUMPTION; Note: R06 concept geometry; dimensions and connections not structurally verified.

# IfcBuildingElementProxy: Limite north · gabião 25 · pedra aparente
In: Lares · Rua das Mercês · artigo 4771
PredefinedType: USERDEFINED; Material: Gabião · pedra irregular
Pset_CasaProvenance - DesignSource: Casa Sobreposta / configuration.json; ReferenceFile: 260617_CasaDFL_Estrutura_Terreno.ifc; ConstructionBasis: DESIGN_ASSUMPTION; Note: R06 concept geometry; dimensions and connections not structurally verified.

# IfcBuildingElementProxy: Limite north · gabião 26 · cesto galvanizado
In: Lares · Rua das Mercês · artigo 4771
PredefinedType: USERDEFINED; Material: Aço galvanizado / Stahl verzinkt
Pset_CasaProvenance - DesignSource: Casa Sobreposta / configuration.json; ReferenceFile: 260617_CasaDFL_Estrutura_Terreno.ifc; ConstructionBasis: DESIGN_ASSUMPTION; Note: R06 concept geometry; dimensions and connections not structurally verified.

# IfcBuildingElementProxy: Limite north · gabião 26 · pedra aparente
In: Lares · Rua das Mercês · artigo 4771
PredefinedType: USERDEFINED; Material: Gabião · pedra irregular
Pset_CasaProvenance - DesignSource: Casa Sobreposta / configuration.json; ReferenceFile: 260617_CasaDFL_Estrutura_Terreno.ifc; ConstructionBasis: DESIGN_ASSUMPTION; Note: R06 concept geometry; dimensions and connections not structurally verified.

# IfcBuildingElementProxy: Limite north · gabião 27 · cesto galvanizado
In: Lares · Rua das Mercês · artigo 4771
PredefinedType: USERDEFINED; Material: Aço galvanizado / Stahl verzinkt
Pset_CasaProvenance - DesignSource: Casa Sobreposta / configuration.json; ReferenceFile: 260617_CasaDFL_Estrutura_Terreno.ifc; ConstructionBasis: DESIGN_ASSUMPTION; Note: R06 concept geometry; dimensions and connections not structurally verified.

# IfcBuildingElementProxy: Limite north · gabião 27 · pedra aparente
In: Lares · Rua das Mercês · artigo 4771
PredefinedType: USERDEFINED; Material: Gabião · pedra irregular
Pset_CasaProvenance - DesignSource: Casa Sobreposta / configuration.json; ReferenceFile: 260617_CasaDFL_Estrutura_Terreno.ifc; ConstructionBasis: DESIGN_ASSUMPTION; Note: R06 concept geometry; dimensions and connections not structurally verified.

# IfcBuildingElementProxy: Limite north · gabião 4 · cesto galvanizado
In: Lares · Rua das Mercês · artigo 4771
PredefinedType: USERDEFINED; Material: Aço galvanizado / Stahl verzinkt
Pset_CasaProvenance - DesignSource: Casa Sobreposta / configuration.json; ReferenceFile: 260617_CasaDFL_Estrutura_Terreno.ifc; ConstructionBasis: DESIGN_ASSUMPTION; Note: R06 concept geometry; dimensions and connections not structurally verified.

# IfcBuildingElementProxy: Limite north · gabião 4 · pedra aparente
In: Lares · Rua das Mercês · artigo 4771
PredefinedType: USERDEFINED; Material: Gabião · pedra irregular
Pset_CasaProvenance - DesignSource: Casa Sobreposta / configuration.json; ReferenceFile: 260617_CasaDFL_Estrutura_Terreno.ifc; ConstructionBasis: DESIGN_ASSUMPTION; Note: R06 concept geometry; dimensions and connections not structurally verified.

# IfcBuildingElementProxy: Limite north · gabião 5 · cesto galvanizado
In: Lares · Rua das Mercês · artigo 4771
PredefinedType: USERDEFINED; Material: Aço galvanizado / Stahl verzinkt
Pset_CasaProvenance - DesignSource: Casa Sobreposta / configuration.json; ReferenceFile: 260617_CasaDFL_Estrutura_Terreno.ifc; ConstructionBasis: DESIGN_ASSUMPTION; Note: R06 concept geometry; dimensions and connections not structurally verified.

# IfcBuildingElementProxy: Limite north · gabião 5 · pedra aparente
In: Lares · Rua das Mercês · artigo 4771
PredefinedType: USERDEFINED; Material: Gabião · pedra irregular
Pset_CasaProvenance - DesignSource: Casa Sobreposta / configuration.json; ReferenceFile: 260617_CasaDFL_Estrutura_Terreno.ifc; ConstructionBasis: DESIGN_ASSUMPTION; Note: R06 concept geometry; dimensions and connections not structurally verified.

# IfcBuildingElementProxy: Limite north · gabião 6 · cesto galvanizado
In: Lares · Rua das Mercês · artigo 4771
PredefinedType: USERDEFINED; Material: Aço galvanizado / Stahl verzinkt
Pset_CasaProvenance - DesignSource: Casa Sobreposta / configuration.json; ReferenceFile: 260617_CasaDFL_Estrutura_Terreno.ifc; ConstructionBasis: DESIGN_ASSUMPTION; Note: R06 concept geometry; dimensions and connections not structurally verified.

# IfcBuildingElementProxy: Limite north · gabião 6 · pedra aparente
In: Lares · Rua das Mercês · artigo 4771
PredefinedType: USERDEFINED; Material: Gabião · pedra irregular
Pset_CasaProvenance - DesignSource: Casa Sobreposta / configuration.json; ReferenceFile: 260617_CasaDFL_Estrutura_Terreno.ifc; ConstructionBasis: DESIGN_ASSUMPTION; Note: R06 concept geometry; dimensions and connections not structurally verified.

# IfcBuildingElementProxy: Limite north · gabião 7 · cesto galvanizado
In: Lares · Rua das Mercês · artigo 4771
PredefinedType: USERDEFINED; Material: Aço galvanizado / Stahl verzinkt
Pset_CasaProvenance - DesignSource: Casa Sobreposta / configuration.json; ReferenceFile: 260617_CasaDFL_Estrutura_Terreno.ifc; ConstructionBasis: DESIGN_ASSUMPTION; Note: R06 concept geometry; dimensions and connections not structurally verified.

# IfcBuildingElementProxy: Limite north · gabião 7 · pedra aparente
In: Lares · Rua das Mercês · artigo 4771
PredefinedType: USERDEFINED; Material: Gabião · pedra irregular
Pset_CasaProvenance - DesignSource: Casa Sobreposta / configuration.json; ReferenceFile: 260617_CasaDFL_Estrutura_Terreno.ifc; ConstructionBasis: DESIGN_ASSUMPTION; Note: R06 concept geometry; dimensions and connections not structurally verified.

# IfcBuildingElementProxy: Limite north · gabião 8 · cesto galvanizado
In: Lares · Rua das Mercês · artigo 4771
PredefinedType: USERDEFINED; Material: Aço galvanizado / Stahl verzinkt
Pset_CasaProvenance - DesignSource: Casa Sobreposta / configuration.json; ReferenceFile: 260617_CasaDFL_Estrutura_Terreno.ifc; ConstructionBasis: DESIGN_ASSUMPTION; Note: R06 concept geometry; dimensions and connections not structurally verified.

# IfcBuildingElementProxy: Limite north · gabião 8 · pedra aparente
In: Lares · Rua das Mercês · artigo 4771
PredefinedType: USERDEFINED; Material: Gabião · pedra irregular
Pset_CasaProvenance - DesignSource: Casa Sobreposta / configuration.json; ReferenceFile: 260617_CasaDFL_Estrutura_Terreno.ifc; ConstructionBasis: DESIGN_ASSUMPTION; Note: R06 concept geometry; dimensions and connections not structurally verified.

# IfcBuildingElementProxy: Limite north · gabião 9 · cesto galvanizado
In: Lares · Rua das Mercês · artigo 4771
PredefinedType: USERDEFINED; Material: Aço galvanizado / Stahl verzinkt
Pset_CasaProvenance - DesignSource: Casa Sobreposta / configuration.json; ReferenceFile: 260617_CasaDFL_Estrutura_Terreno.ifc; ConstructionBasis: DESIGN_ASSUMPTION; Note: R06 concept geometry; dimensions and connections not structurally verified.

# IfcBuildingElementProxy: Limite north · gabião 9 · pedra aparente
In: Lares · Rua das Mercês · artigo 4771
PredefinedType: USERDEFINED; Material: Gabião · pedra irregular
Pset_CasaProvenance - DesignSource: Casa Sobreposta / configuration.json; ReferenceFile: 260617_CasaDFL_Estrutura_Terreno.ifc; ConstructionBasis: DESIGN_ASSUMPTION; Note: R06 concept geometry; dimensions and connections not structurally verified.

# IfcBuildingElementProxy: Limite north · vala de interceção (37)
In: Lares · Rua das Mercês · artigo 4771
PredefinedType: USERDEFINED; Material: Brita drenante
Pset_CasaProvenance - DesignSource: Casa Sobreposta / configuration.json; ReferenceFile: 260617_CasaDFL_Estrutura_Terreno.ifc; ConstructionBasis: DESIGN_ASSUMPTION

# IfcBuildingElementProxy: Limite south · gabião 1 · cesto galvanizado
In: Lares · Rua das Mercês · artigo 4771
PredefinedType: USERDEFINED; Material: Aço galvanizado / Stahl verzinkt
Pset_CasaProvenance - DesignSource: Casa Sobreposta / configuration.json; ReferenceFile: 260617_CasaDFL_Estrutura_Terreno.ifc; ConstructionBasis: DESIGN_ASSUMPTION; Note: R06 concept geometry; dimensions and connections not structurally verified.

# IfcBuildingElementProxy: Limite south · gabião 1 · pedra aparente
In: Lares · Rua das Mercês · artigo 4771
PredefinedType: USERDEFINED; Material: Gabião · pedra irregular
Pset_CasaProvenance - DesignSource: Casa Sobreposta / configuration.json; ReferenceFile: 260617_CasaDFL_Estrutura_Terreno.ifc; ConstructionBasis: DESIGN_ASSUMPTION; Note: R06 concept geometry; dimensions and connections not structurally verified.

# IfcBuildingElementProxy: Limite south · gabião 10 · cesto galvanizado
In: Lares · Rua das Mercês · artigo 4771
PredefinedType: USERDEFINED; Material: Aço galvanizado / Stahl verzinkt
Pset_CasaProvenance - DesignSource: Casa Sobreposta / configuration.json; ReferenceFile: 260617_CasaDFL_Estrutura_Terreno.ifc; ConstructionBasis: DESIGN_ASSUMPTION; Note: R06 concept geometry; dimensions and connections not structurally verified.

# IfcBuildingElementProxy: Limite south · gabião 10 · pedra aparente
In: Lares · Rua das Mercês · artigo 4771
PredefinedType: USERDEFINED; Material: Gabião · pedra irregular
Pset_CasaProvenance - DesignSource: Casa Sobreposta / configuration.json; ReferenceFile: 260617_CasaDFL_Estrutura_Terreno.ifc; ConstructionBasis: DESIGN_ASSUMPTION; Note: R06 concept geometry; dimensions and connections not structurally verified.

# IfcBuildingElementProxy: Limite south · gabião 11 · cesto galvanizado
In: Lares · Rua das Mercês · artigo 4771
PredefinedType: USERDEFINED; Material: Aço galvanizado / Stahl verzinkt
Pset_CasaProvenance - DesignSource: Casa Sobreposta / configuration.json; ReferenceFile: 260617_CasaDFL_Estrutura_Terreno.ifc; ConstructionBasis: DESIGN_ASSUMPTION; Note: R06 concept geometry; dimensions and connections not structurally verified.

# IfcBuildingElementProxy: Limite south · gabião 11 · pedra aparente
In: Lares · Rua das Mercês · artigo 4771
PredefinedType: USERDEFINED; Material: Gabião · pedra irregular
Pset_CasaProvenance - DesignSource: Casa Sobreposta / configuration.json; ReferenceFile: 260617_CasaDFL_Estrutura_Terreno.ifc; ConstructionBasis: DESIGN_ASSUMPTION; Note: R06 concept geometry; dimensions and connections not structurally verified.

# IfcBuildingElementProxy: Limite south · gabião 12 · cesto galvanizado
In: Lares · Rua das Mercês · artigo 4771
PredefinedType: USERDEFINED; Material: Aço galvanizado / Stahl verzinkt
Pset_CasaProvenance - DesignSource: Casa Sobreposta / configuration.json; ReferenceFile: 260617_CasaDFL_Estrutura_Terreno.ifc; ConstructionBasis: DESIGN_ASSUMPTION; Note: R06 concept geometry; dimensions and connections not structurally verified.

# IfcBuildingElementProxy: Limite south · gabião 12 · pedra aparente
In: Lares · Rua das Mercês · artigo 4771
PredefinedType: USERDEFINED; Material: Gabião · pedra irregular
Pset_CasaProvenance - DesignSource: Casa Sobreposta / configuration.json; ReferenceFile: 260617_CasaDFL_Estrutura_Terreno.ifc; ConstructionBasis: DESIGN_ASSUMPTION; Note: R06 concept geometry; dimensions and connections not structurally verified.

# IfcBuildingElementProxy: Limite south · gabião 13 · cesto galvanizado
In: Lares · Rua das Mercês · artigo 4771
PredefinedType: USERDEFINED; Material: Aço galvanizado / Stahl verzinkt
Pset_CasaProvenance - DesignSource: Casa Sobreposta / configuration.json; ReferenceFile: 260617_CasaDFL_Estrutura_Terreno.ifc; ConstructionBasis: DESIGN_ASSUMPTION; Note: R06 concept geometry; dimensions and connections not structurally verified.

# IfcBuildingElementProxy: Limite south · gabião 13 · pedra aparente
In: Lares · Rua das Mercês · artigo 4771
PredefinedType: USERDEFINED; Material: Gabião · pedra irregular
Pset_CasaProvenance - DesignSource: Casa Sobreposta / configuration.json; ReferenceFile: 260617_CasaDFL_Estrutura_Terreno.ifc; ConstructionBasis: DESIGN_ASSUMPTION; Note: R06 concept geometry; dimensions and connections not structurally verified.

# IfcBuildingElementProxy: Limite south · gabião 14 · cesto galvanizado
In: Lares · Rua das Mercês · artigo 4771
PredefinedType: USERDEFINED; Material: Aço galvanizado / Stahl verzinkt
Pset_CasaProvenance - DesignSource: Casa Sobreposta / configuration.json; ReferenceFile: 260617_CasaDFL_Estrutura_Terreno.ifc; ConstructionBasis: DESIGN_ASSUMPTION; Note: R06 concept geometry; dimensions and connections not structurally verified.

# IfcBuildingElementProxy: Limite south · gabião 14 · pedra aparente
In: Lares · Rua das Mercês · artigo 4771
PredefinedType: USERDEFINED; Material: Gabião · pedra irregular
Pset_CasaProvenance - DesignSource: Casa Sobreposta / configuration.json; ReferenceFile: 260617_CasaDFL_Estrutura_Terreno.ifc; ConstructionBasis: DESIGN_ASSUMPTION; Note: R06 concept geometry; dimensions and connections not structurally verified.

# IfcBuildingElementProxy: Limite south · gabião 15 · cesto galvanizado
In: Lares · Rua das Mercês · artigo 4771
PredefinedType: USERDEFINED; Material: Aço galvanizado / Stahl verzinkt
Pset_CasaProvenance - DesignSource: Casa Sobreposta / configuration.json; ReferenceFile: 260617_CasaDFL_Estrutura_Terreno.ifc; ConstructionBasis: DESIGN_ASSUMPTION; Note: R06 concept geometry; dimensions and connections not structurally verified.

# IfcBuildingElementProxy: Limite south · gabião 15 · pedra aparente
In: Lares · Rua das Mercês · artigo 4771
PredefinedType: USERDEFINED; Material: Gabião · pedra irregular
Pset_CasaProvenance - DesignSource: Casa Sobreposta / configuration.json; ReferenceFile: 260617_CasaDFL_Estrutura_Terreno.ifc; ConstructionBasis: DESIGN_ASSUMPTION; Note: R06 concept geometry; dimensions and connections not structurally verified.

# IfcBuildingElementProxy: Limite south · gabião 16 · cesto galvanizado
In: Lares · Rua das Mercês · artigo 4771
PredefinedType: USERDEFINED; Material: Aço galvanizado / Stahl verzinkt
Pset_CasaProvenance - DesignSource: Casa Sobreposta / configuration.json; ReferenceFile: 260617_CasaDFL_Estrutura_Terreno.ifc; ConstructionBasis: DESIGN_ASSUMPTION; Note: R06 concept geometry; dimensions and connections not structurally verified.

# IfcBuildingElementProxy: Limite south · gabião 16 · pedra aparente
In: Lares · Rua das Mercês · artigo 4771
PredefinedType: USERDEFINED; Material: Gabião · pedra irregular
Pset_CasaProvenance - DesignSource: Casa Sobreposta / configuration.json; ReferenceFile: 260617_CasaDFL_Estrutura_Terreno.ifc; ConstructionBasis: DESIGN_ASSUMPTION; Note: R06 concept geometry; dimensions and connections not structurally verified.

# IfcBuildingElementProxy: Limite south · gabião 17 · cesto galvanizado
In: Lares · Rua das Mercês · artigo 4771
PredefinedType: USERDEFINED; Material: Aço galvanizado / Stahl verzinkt
Pset_CasaProvenance - DesignSource: Casa Sobreposta / configuration.json; ReferenceFile: 260617_CasaDFL_Estrutura_Terreno.ifc; ConstructionBasis: DESIGN_ASSUMPTION; Note: R06 concept geometry; dimensions and connections not structurally verified.

# IfcBuildingElementProxy: Limite south · gabião 17 · pedra aparente
In: Lares · Rua das Mercês · artigo 4771
PredefinedType: USERDEFINED; Material: Gabião · pedra irregular
Pset_CasaProvenance - DesignSource: Casa Sobreposta / configuration.json; ReferenceFile: 260617_CasaDFL_Estrutura_Terreno.ifc; ConstructionBasis: DESIGN_ASSUMPTION; Note: R06 concept geometry; dimensions and connections not structurally verified.

# IfcBuildingElementProxy: Limite south · gabião 18 · cesto galvanizado
In: Lares · Rua das Mercês · artigo 4771
PredefinedType: USERDEFINED; Material: Aço galvanizado / Stahl verzinkt
Pset_CasaProvenance - DesignSource: Casa Sobreposta / configuration.json; ReferenceFile: 260617_CasaDFL_Estrutura_Terreno.ifc; ConstructionBasis: DESIGN_ASSUMPTION; Note: R06 concept geometry; dimensions and connections not structurally verified.

# IfcBuildingElementProxy: Limite south · gabião 18 · pedra aparente
In: Lares · Rua das Mercês · artigo 4771
PredefinedType: USERDEFINED; Material: Gabião · pedra irregular
Pset_CasaProvenance - DesignSource: Casa Sobreposta / configuration.json; ReferenceFile: 260617_CasaDFL_Estrutura_Terreno.ifc; ConstructionBasis: DESIGN_ASSUMPTION; Note: R06 concept geometry; dimensions and connections not structurally verified.

# IfcBuildingElementProxy: Limite south · gabião 19 · cesto galvanizado
In: Lares · Rua das Mercês · artigo 4771
PredefinedType: USERDEFINED; Material: Aço galvanizado / Stahl verzinkt
Pset_CasaProvenance - DesignSource: Casa Sobreposta / configuration.json; ReferenceFile: 260617_CasaDFL_Estrutura_Terreno.ifc; ConstructionBasis: DESIGN_ASSUMPTION; Note: R06 concept geometry; dimensions and connections not structurally verified.

# IfcBuildingElementProxy: Limite south · gabião 19 · pedra aparente
In: Lares · Rua das Mercês · artigo 4771
PredefinedType: USERDEFINED; Material: Gabião · pedra irregular
Pset_CasaProvenance - DesignSource: Casa Sobreposta / configuration.json; ReferenceFile: 260617_CasaDFL_Estrutura_Terreno.ifc; ConstructionBasis: DESIGN_ASSUMPTION; Note: R06 concept geometry; dimensions and connections not structurally verified.

# IfcBuildingElementProxy: Limite south · gabião 2 · cesto galvanizado
In: Lares · Rua das Mercês · artigo 4771
PredefinedType: USERDEFINED; Material: Aço galvanizado / Stahl verzinkt
Pset_CasaProvenance - DesignSource: Casa Sobreposta / configuration.json; ReferenceFile: 260617_CasaDFL_Estrutura_Terreno.ifc; ConstructionBasis: DESIGN_ASSUMPTION; Note: R06 concept geometry; dimensions and connections not structurally verified.

# IfcBuildingElementProxy: Limite south · gabião 2 · pedra aparente
In: Lares · Rua das Mercês · artigo 4771
PredefinedType: USERDEFINED; Material: Gabião · pedra irregular
Pset_CasaProvenance - DesignSource: Casa Sobreposta / configuration.json; ReferenceFile: 260617_CasaDFL_Estrutura_Terreno.ifc; ConstructionBasis: DESIGN_ASSUMPTION; Note: R06 concept geometry; dimensions and connections not structurally verified.

# IfcBuildingElementProxy: Limite south · gabião 20 · cesto galvanizado
In: Lares · Rua das Mercês · artigo 4771
PredefinedType: USERDEFINED; Material: Aço galvanizado / Stahl verzinkt
Pset_CasaProvenance - DesignSource: Casa Sobreposta / configuration.json; ReferenceFile: 260617_CasaDFL_Estrutura_Terreno.ifc; ConstructionBasis: DESIGN_ASSUMPTION; Note: R06 concept geometry; dimensions and connections not structurally verified.

# IfcBuildingElementProxy: Limite south · gabião 20 · pedra aparente
In: Lares · Rua das Mercês · artigo 4771
PredefinedType: USERDEFINED; Material: Gabião · pedra irregular
Pset_CasaProvenance - DesignSource: Casa Sobreposta / configuration.json; ReferenceFile: 260617_CasaDFL_Estrutura_Terreno.ifc; ConstructionBasis: DESIGN_ASSUMPTION; Note: R06 concept geometry; dimensions and connections not structurally verified.

# IfcBuildingElementProxy: Limite south · gabião 21 · cesto galvanizado
In: Lares · Rua das Mercês · artigo 4771
PredefinedType: USERDEFINED; Material: Aço galvanizado / Stahl verzinkt
Pset_CasaProvenance - DesignSource: Casa Sobreposta / configuration.json; ReferenceFile: 260617_CasaDFL_Estrutura_Terreno.ifc; ConstructionBasis: DESIGN_ASSUMPTION; Note: R06 concept geometry; dimensions and connections not structurally verified.

# IfcBuildingElementProxy: Limite south · gabião 21 · pedra aparente
In: Lares · Rua das Mercês · artigo 4771
PredefinedType: USERDEFINED; Material: Gabião · pedra irregular
Pset_CasaProvenance - DesignSource: Casa Sobreposta / configuration.json; ReferenceFile: 260617_CasaDFL_Estrutura_Terreno.ifc; ConstructionBasis: DESIGN_ASSUMPTION; Note: R06 concept geometry; dimensions and connections not structurally verified.

# IfcBuildingElementProxy: Limite south · gabião 22 · cesto galvanizado
In: Lares · Rua das Mercês · artigo 4771
PredefinedType: USERDEFINED; Material: Aço galvanizado / Stahl verzinkt
Pset_CasaProvenance - DesignSource: Casa Sobreposta / configuration.json; ReferenceFile: 260617_CasaDFL_Estrutura_Terreno.ifc; ConstructionBasis: DESIGN_ASSUMPTION; Note: R06 concept geometry; dimensions and connections not structurally verified.

# IfcBuildingElementProxy: Limite south · gabião 22 · pedra aparente
In: Lares · Rua das Mercês · artigo 4771
PredefinedType: USERDEFINED; Material: Gabião · pedra irregular
Pset_CasaProvenance - DesignSource: Casa Sobreposta / configuration.json; ReferenceFile: 260617_CasaDFL_Estrutura_Terreno.ifc; ConstructionBasis: DESIGN_ASSUMPTION; Note: R06 concept geometry; dimensions and connections not structurally verified.
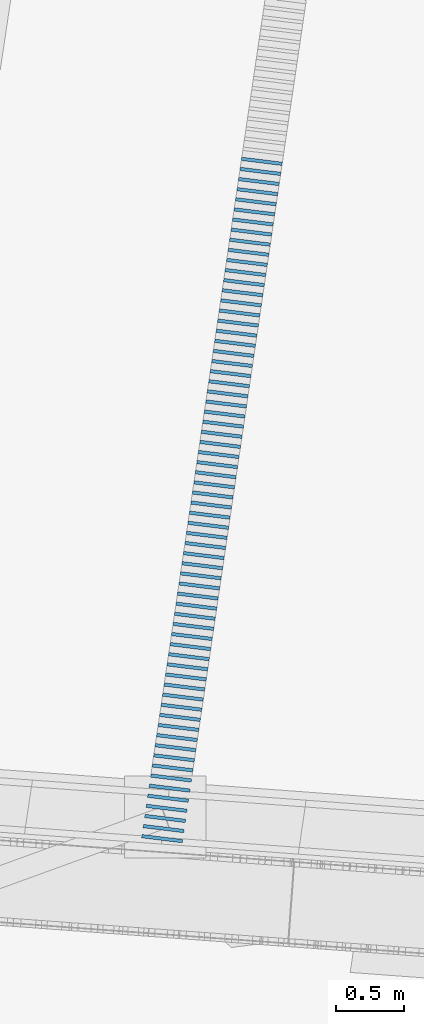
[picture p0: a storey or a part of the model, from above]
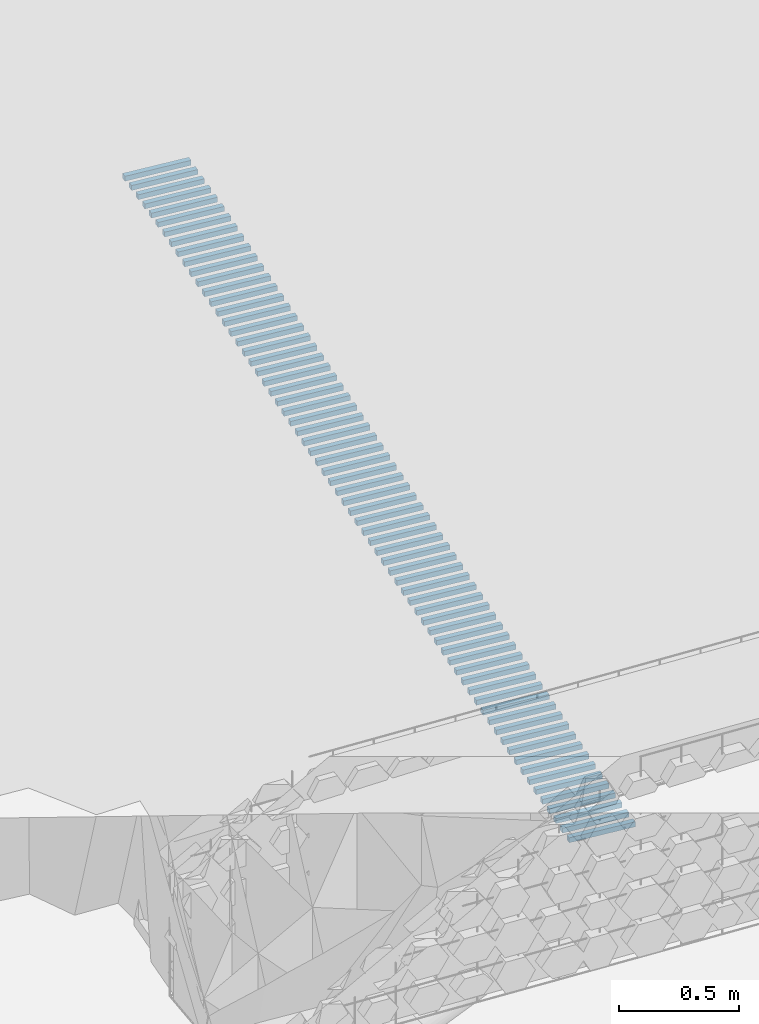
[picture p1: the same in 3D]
Properties of the parts of a building model (IFC4), part 3 of 3

# IfcWall: Acesso · gabião 1 27.0 · núcleo de pedra
Pset_CasaProvenance - DesignSource: Casa Sobreposta / configuration.json; ReferenceFile: 260617_CasaDFL_Estrutura_Terreno.ifc; ConstructionBasis: DESIGN_ASSUMPTION; Note: Concept gabion envelope; mesh gauge, foundation, filter and retaining capacity to design.
Pset_CasaBoundary - BaseSurveyLevel_m: 15.2281; TopSurveyLevel_m: 16.3757; Status: CONCEPT_NOT_SIZED

# IfcWall: Acesso · gabião 1 3.0 · núcleo de pedra
In: Lares · Rua das Mercês · artigo 4771
PredefinedType: USERDEFINED; Material: Gabião · enchimento
Pset_CasaProvenance - DesignSource: Casa Sobreposta / configuration.json; ReferenceFile: 260617_CasaDFL_Estrutura_Terreno.ifc; ConstructionBasis: DESIGN_ASSUMPTION; Note: Concept gabion envelope; mesh gauge, foundation, filter and retaining capacity to design.
Pset_CasaBoundary - BaseSurveyLevel_m: 13.43; TopSurveyLevel_m: 15.2188; Status: CONCEPT_NOT_SIZED

# IfcWall: Acesso · gabião 1 30.0 · núcleo de pedra
In: Lares · Rua das Mercês · artigo 4771
PredefinedType: USERDEFINED; Material: Gabião · enchimento
Pset_CasaProvenance - DesignSource: Casa Sobreposta / configuration.json; ReferenceFile: 260617_CasaDFL_Estrutura_Terreno.ifc; ConstructionBasis: DESIGN_ASSUMPTION; Note: Concept gabion envelope; mesh gauge, foundation, filter and retaining capacity to design.
Pset_CasaBoundary - BaseSurveyLevel_m: 15.4515; TopSurveyLevel_m: 16.5071; Status: CONCEPT_NOT_SIZED

# IfcWall: Acesso · gabião 1 33.0 · núcleo de pedra
In: Lares · Rua das Mercês · artigo 4771
PredefinedType: USERDEFINED; Material: Gabião · enchimento
Pset_CasaProvenance - DesignSource: Casa Sobreposta / configuration.json; ReferenceFile: 260617_CasaDFL_Estrutura_Terreno.ifc; ConstructionBasis: DESIGN_ASSUMPTION; Note: Concept gabion envelope; mesh gauge, foundation, filter and retaining capacity to design.
Pset_CasaBoundary - BaseSurveyLevel_m: 15.6748; TopSurveyLevel_m: 16.6061; Status: CONCEPT_NOT_SIZED

# IfcWall: Acesso · gabião 1 6.0 · núcleo de pedra
In: Lares · Rua das Mercês · artigo 4771
PredefinedType: USERDEFINED; Material: Gabião · enchimento
Pset_CasaProvenance - DesignSource: Casa Sobreposta / configuration.json; ReferenceFile: 260617_CasaDFL_Estrutura_Terreno.ifc; ConstructionBasis: DESIGN_ASSUMPTION; Note: Concept gabion envelope; mesh gauge, foundation, filter and retaining capacity to design.
Pset_CasaBoundary - BaseSurveyLevel_m: 13.6645; TopSurveyLevel_m: 15.2784; Status: CONCEPT_NOT_SIZED

# IfcWall: Acesso · gabião 1 9.0 · núcleo de pedra
In: Lares · Rua das Mercês · artigo 4771
PredefinedType: USERDEFINED; Material: Gabião · enchimento
Pset_CasaProvenance - DesignSource: Casa Sobreposta / configuration.json; ReferenceFile: 260617_CasaDFL_Estrutura_Terreno.ifc; ConstructionBasis: DESIGN_ASSUMPTION; Note: Concept gabion envelope; mesh gauge, foundation, filter and retaining capacity to design.
Pset_CasaBoundary - BaseSurveyLevel_m: 13.8878; TopSurveyLevel_m: 15.3146; Status: CONCEPT_NOT_SIZED

# IfcWall: Cisterna · parede nascente
In: -01 · Cisterna sob o terraço
PredefinedType: USERDEFINED; Material: Betão armado / Stahlbeton
Pset_CasaProvenance - DesignSource: Casa Sobreposta / configuration.json; ReferenceFile: 260617_CasaDFL_Estrutura_Terreno.ifc; ConstructionBasis: DESIGN_ASSUMPTION; Note: 250 mm RC study wall, waterproofing and joints to detail; no retaining capacity asserted.

# IfcWall: Cisterna · parede norte
In: -01 · Cisterna sob o terraço
PredefinedType: USERDEFINED; Material: Betão armado / Stahlbeton
Pset_CasaProvenance - DesignSource: Casa Sobreposta / configuration.json; ReferenceFile: 260617_CasaDFL_Estrutura_Terreno.ifc; ConstructionBasis: DESIGN_ASSUMPTION; Note: 250 mm RC study wall, waterproofing and joints to detail; no retaining capacity asserted.

# IfcWall: Cisterna · parede poente
In: -01 · Cisterna sob o terraço
PredefinedType: USERDEFINED; Material: Betão armado / Stahlbeton
Pset_CasaProvenance - DesignSource: Casa Sobreposta / configuration.json; ReferenceFile: 260617_CasaDFL_Estrutura_Terreno.ifc; ConstructionBasis: DESIGN_ASSUMPTION; Note: 250 mm RC study wall, waterproofing and joints to detail; no retaining capacity asserted.

# IfcWall: Cisterna · parede sul
In: -01 · Cisterna sob o terraço
PredefinedType: USERDEFINED; Material: Betão armado / Stahlbeton
Pset_CasaProvenance - DesignSource: Casa Sobreposta / configuration.json; ReferenceFile: 260617_CasaDFL_Estrutura_Terreno.ifc; ConstructionBasis: DESIGN_ASSUMPTION; Note: 250 mm RC study wall, waterproofing and joints to detail; no retaining capacity asserted.

# IfcWall: Limite north · gabião 10 · núcleo de pedra
In: Lares · Rua das Mercês · artigo 4771
PredefinedType: USERDEFINED; Material: Gabião · enchimento
Pset_CasaProvenance - DesignSource: Casa Sobreposta / configuration.json; ReferenceFile: 260617_CasaDFL_Estrutura_Terreno.ifc; ConstructionBasis: DESIGN_ASSUMPTION; Note: Concept gabion envelope; mesh gauge, foundation, filter and retaining capacity to design.
Pset_CasaBoundary - BaseSurveyLevel_m: 14; TopSurveyLevel_m: 14.9; Status: CONCEPT_NOT_SIZED

# IfcWall: Limite north · gabião 11 · núcleo de pedra
In: Lares · Rua das Mercês · artigo 4771
PredefinedType: USERDEFINED; Material: Gabião · enchimento
Pset_CasaProvenance - DesignSource: Casa Sobreposta / configuration.json; ReferenceFile: 260617_CasaDFL_Estrutura_Terreno.ifc; ConstructionBasis: DESIGN_ASSUMPTION; Note: Concept gabion envelope; mesh gauge, foundation, filter and retaining capacity to design.
Pset_CasaBoundary - BaseSurveyLevel_m: 14.25; TopSurveyLevel_m: 15; Status: CONCEPT_NOT_SIZED

# IfcWall: Limite north · gabião 12 · núcleo de pedra
In: Lares · Rua das Mercês · artigo 4771
PredefinedType: USERDEFINED; Material: Gabião · enchimento
Pset_CasaProvenance - DesignSource: Casa Sobreposta / configuration.json; ReferenceFile: 260617_CasaDFL_Estrutura_Terreno.ifc; ConstructionBasis: DESIGN_ASSUMPTION; Note: Concept gabion envelope; mesh gauge, foundation, filter and retaining capacity to design.
Pset_CasaBoundary - BaseSurveyLevel_m: 14.25; TopSurveyLevel_m: 15.1; Status: CONCEPT_NOT_SIZED

# IfcWall: Limite north · gabião 13 · núcleo de pedra
In: Lares · Rua das Mercês · artigo 4771
PredefinedType: USERDEFINED; Material: Gabião · enchimento
Pset_CasaProvenance - DesignSource: Casa Sobreposta / configuration.json; ReferenceFile: 260617_CasaDFL_Estrutura_Terreno.ifc; ConstructionBasis: DESIGN_ASSUMPTION; Note: Concept gabion envelope; mesh gauge, foundation, filter and retaining capacity to design.
Pset_CasaBoundary - BaseSurveyLevel_m: 14.25; TopSurveyLevel_m: 15.2; Status: CONCEPT_NOT_SIZED

# IfcWall: Limite north · gabião 14 · núcleo de pedra
In: Lares · Rua das Mercês · artigo 4771
PredefinedType: USERDEFINED; Material: Gabião · enchimento
Pset_CasaProvenance - DesignSource: Casa Sobreposta / configuration.json; ReferenceFile: 260617_CasaDFL_Estrutura_Terreno.ifc; ConstructionBasis: DESIGN_ASSUMPTION; Note: Concept gabion envelope; mesh gauge, foundation, filter and retaining capacity to design.
Pset_CasaBoundary - BaseSurveyLevel_m: 14.5; TopSurveyLevel_m: 15.3; Status: CONCEPT_NOT_SIZED

# IfcWall: Limite north · gabião 15 · núcleo de pedra
In: Lares · Rua das Mercês · artigo 4771
PredefinedType: USERDEFINED; Material: Gabião · enchimento
Pset_CasaProvenance - DesignSource: Casa Sobreposta / configuration.json; ReferenceFile: 260617_CasaDFL_Estrutura_Terreno.ifc; ConstructionBasis: DESIGN_ASSUMPTION; Note: Concept gabion envelope; mesh gauge, foundation, filter and retaining capacity to design.
Pset_CasaBoundary - BaseSurveyLevel_m: 14.5; TopSurveyLevel_m: 15.5; Status: CONCEPT_NOT_SIZED

# IfcWall: Limite north · gabião 16 · núcleo de pedra
In: Lares · Rua das Mercês · artigo 4771
PredefinedType: USERDEFINED; Material: Gabião · enchimento
Pset_CasaProvenance - DesignSource: Casa Sobreposta / configuration.json; ReferenceFile: 260617_CasaDFL_Estrutura_Terreno.ifc; ConstructionBasis: DESIGN_ASSUMPTION; Note: Concept gabion envelope; mesh gauge, foundation, filter and retaining capacity to design.
Pset_CasaBoundary - BaseSurveyLevel_m: 14.75; TopSurveyLevel_m: 15.5; Status: CONCEPT_NOT_SIZED

# IfcWall: Limite north · gabião 17 · núcleo de pedra
In: Lares · Rua das Mercês · artigo 4771
PredefinedType: USERDEFINED; Material: Gabião · enchimento
Pset_CasaProvenance - DesignSource: Casa Sobreposta / configuration.json; ReferenceFile: 260617_CasaDFL_Estrutura_Terreno.ifc; ConstructionBasis: DESIGN_ASSUMPTION; Note: Concept gabion envelope; mesh gauge, foundation, filter and retaining capacity to design.
Pset_CasaBoundary - BaseSurveyLevel_m: 14.75; TopSurveyLevel_m: 15.6; Status: CONCEPT_NOT_SIZED

# IfcWall: Limite north · gabião 18 · núcleo de pedra
In: Lares · Rua das Mercês · artigo 4771
PredefinedType: USERDEFINED; Material: Gabião · enchimento
Pset_CasaProvenance - DesignSource: Casa Sobreposta / configuration.json; ReferenceFile: 260617_CasaDFL_Estrutura_Terreno.ifc; ConstructionBasis: DESIGN_ASSUMPTION; Note: Concept gabion envelope; mesh gauge, foundation, filter and retaining capacity to design.
Pset_CasaBoundary - BaseSurveyLevel_m: 14.75; TopSurveyLevel_m: 15.6; Status: CONCEPT_NOT_SIZED

# IfcWall: Limite north · gabião 19 · núcleo de pedra
In: Lares · Rua das Mercês · artigo 4771
PredefinedType: USERDEFINED; Material: Gabião · enchimento
Pset_CasaProvenance - DesignSource: Casa Sobreposta / configuration.json; ReferenceFile: 260617_CasaDFL_Estrutura_Terreno.ifc; ConstructionBasis: DESIGN_ASSUMPTION; Note: Concept gabion envelope; mesh gauge, foundation, filter and retaining capacity to design.
Pset_CasaBoundary - BaseSurveyLevel_m: 14.75; TopSurveyLevel_m: 15.7; Status: CONCEPT_NOT_SIZED

# IfcWall: Limite north · gabião 20 · núcleo de pedra
In: Lares · Rua das Mercês · artigo 4771
PredefinedType: USERDEFINED; Material: Gabião · enchimento
Pset_CasaProvenance - DesignSource: Casa Sobreposta / configuration.json; ReferenceFile: 260617_CasaDFL_Estrutura_Terreno.ifc; ConstructionBasis: DESIGN_ASSUMPTION; Note: Concept gabion envelope; mesh gauge, foundation, filter and retaining capacity to design.
Pset_CasaBoundary - BaseSurveyLevel_m: 15; TopSurveyLevel_m: 15.7; Status: CONCEPT_NOT_SIZED

# IfcWall: Limite north · gabião 21 · núcleo de pedra
In: Lares · Rua das Mercês · artigo 4771
PredefinedType: USERDEFINED; Material: Gabião · enchimento
Pset_CasaProvenance - DesignSource: Casa Sobreposta / configuration.json; ReferenceFile: 260617_CasaDFL_Estrutura_Terreno.ifc; ConstructionBasis: DESIGN_ASSUMPTION; Note: Concept gabion envelope; mesh gauge, foundation, filter and retaining capacity to design.
Pset_CasaBoundary - BaseSurveyLevel_m: 15; TopSurveyLevel_m: 15.9; Status: CONCEPT_NOT_SIZED

# IfcWall: Limite north · gabião 22 · núcleo de pedra
In: Lares · Rua das Mercês · artigo 4771
PredefinedType: USERDEFINED; Material: Gabião · enchimento
Pset_CasaProvenance - DesignSource: Casa Sobreposta / configuration.json; ReferenceFile: 260617_CasaDFL_Estrutura_Terreno.ifc; ConstructionBasis: DESIGN_ASSUMPTION; Note: Concept gabion envelope; mesh gauge, foundation, filter and retaining capacity to design.
Pset_CasaBoundary - BaseSurveyLevel_m: 15.25; TopSurveyLevel_m: 16.1; Status: CONCEPT_NOT_SIZED

# IfcWall: Limite north · gabião 23 · núcleo de pedra
In: Lares · Rua das Mercês · artigo 4771
PredefinedType: USERDEFINED; Material: Gabião · enchimento
Pset_CasaProvenance - DesignSource: Casa Sobreposta / configuration.json; ReferenceFile: 260617_CasaDFL_Estrutura_Terreno.ifc; ConstructionBasis: DESIGN_ASSUMPTION; Note: Concept gabion envelope; mesh gauge, foundation, filter and retaining capacity to design.
Pset_CasaBoundary - BaseSurveyLevel_m: 15.25; TopSurveyLevel_m: 16.3; Status: CONCEPT_NOT_SIZED

# IfcWall: Limite north · gabião 24 · núcleo de pedra
In: Lares · Rua das Mercês · artigo 4771
PredefinedType: USERDEFINED; Material: Gabião · enchimento
Pset_CasaProvenance - DesignSource: Casa Sobreposta / configuration.json; ReferenceFile: 260617_CasaDFL_Estrutura_Terreno.ifc; ConstructionBasis: DESIGN_ASSUMPTION; Note: Concept gabion envelope; mesh gauge, foundation, filter and retaining capacity to design.
Pset_CasaBoundary - BaseSurveyLevel_m: 15.5; TopSurveyLevel_m: 16.5; Status: CONCEPT_NOT_SIZED

# IfcWall: Limite north · gabião 25 · núcleo de pedra
In: Lares · Rua das Mercês · artigo 4771
PredefinedType: USERDEFINED; Material: Gabião · enchimento
Pset_CasaProvenance - DesignSource: Casa Sobreposta / configuration.json; ReferenceFile: 260617_CasaDFL_Estrutura_Terreno.ifc; ConstructionBasis: DESIGN_ASSUMPTION; Note: Concept gabion envelope; mesh gauge, foundation, filter and retaining capacity to design.
Pset_CasaBoundary - BaseSurveyLevel_m: 15.75; TopSurveyLevel_m: 16.6; Status: CONCEPT_NOT_SIZED

# IfcWall: Limite north · gabião 26 · núcleo de pedra
In: Lares · Rua das Mercês · artigo 4771
PredefinedType: USERDEFINED; Material: Gabião · enchimento
Pset_CasaProvenance - DesignSource: Casa Sobreposta / configuration.json; ReferenceFile: 260617_CasaDFL_Estrutura_Terreno.ifc; ConstructionBasis: DESIGN_ASSUMPTION; Note: Concept gabion envelope; mesh gauge, foundation, filter and retaining capacity to design.
Pset_CasaBoundary - BaseSurveyLevel_m: 15.75; TopSurveyLevel_m: 16.8; Status: CONCEPT_NOT_SIZED

# IfcWall: Limite north · gabião 27 · núcleo de pedra
In: Lares · Rua das Mercês · artigo 4771
PredefinedType: USERDEFINED; Material: Gabião · enchimento
Pset_CasaProvenance - DesignSource: Casa Sobreposta / configuration.json; ReferenceFile: 260617_CasaDFL_Estrutura_Terreno.ifc; ConstructionBasis: DESIGN_ASSUMPTION; Note: Concept gabion envelope; mesh gauge, foundation, filter and retaining capacity to design.
Pset_CasaBoundary - BaseSurveyLevel_m: 16; TopSurveyLevel_m: 16.9; Status: CONCEPT_NOT_SIZED

# IfcWall: Limite north · gabião 4 · núcleo de pedra
In: Lares · Rua das Mercês · artigo 4771
PredefinedType: USERDEFINED; Material: Gabião · enchimento
Pset_CasaProvenance - DesignSource: Casa Sobreposta / configuration.json; ReferenceFile: 260617_CasaDFL_Estrutura_Terreno.ifc; ConstructionBasis: DESIGN_ASSUMPTION; Note: Concept gabion envelope; mesh gauge, foundation, filter and retaining capacity to design.
Pset_CasaBoundary - BaseSurveyLevel_m: 13.25; TopSurveyLevel_m: 14.3; Status: CONCEPT_NOT_SIZED

# IfcWall: Limite north · gabião 5 · núcleo de pedra
In: Lares · Rua das Mercês · artigo 4771
PredefinedType: USERDEFINED; Material: Gabião · enchimento
Pset_CasaProvenance - DesignSource: Casa Sobreposta / configuration.json; ReferenceFile: 260617_CasaDFL_Estrutura_Terreno.ifc; ConstructionBasis: DESIGN_ASSUMPTION; Note: Concept gabion envelope; mesh gauge, foundation, filter and retaining capacity to design.
Pset_CasaBoundary - BaseSurveyLevel_m: 13.5; TopSurveyLevel_m: 14.3; Status: CONCEPT_NOT_SIZED

# IfcWall: Limite north · gabião 6 · núcleo de pedra
In: Lares · Rua das Mercês · artigo 4771
PredefinedType: USERDEFINED; Material: Gabião · enchimento
Pset_CasaProvenance - DesignSource: Casa Sobreposta / configuration.json; ReferenceFile: 260617_CasaDFL_Estrutura_Terreno.ifc; ConstructionBasis: DESIGN_ASSUMPTION; Note: Concept gabion envelope; mesh gauge, foundation, filter and retaining capacity to design.
Pset_CasaBoundary - BaseSurveyLevel_m: 13.5; TopSurveyLevel_m: 14.5; Status: CONCEPT_NOT_SIZED

# IfcWall: Limite north · gabião 7 · núcleo de pedra
In: Lares · Rua das Mercês · artigo 4771
PredefinedType: USERDEFINED; Material: Gabião · enchimento
Pset_CasaProvenance - DesignSource: Casa Sobreposta / configuration.json; ReferenceFile: 260617_CasaDFL_Estrutura_Terreno.ifc; ConstructionBasis: DESIGN_ASSUMPTION; Note: Concept gabion envelope; mesh gauge, foundation, filter and retaining capacity to design.
Pset_CasaBoundary - BaseSurveyLevel_m: 13.75; TopSurveyLevel_m: 14.7; Status: CONCEPT_NOT_SIZED

# IfcWall: Limite north · gabião 8 · núcleo de pedra
In: Lares · Rua das Mercês · artigo 4771
PredefinedType: USERDEFINED; Material: Gabião · enchimento
Pset_CasaProvenance - DesignSource: Casa Sobreposta / configuration.json; ReferenceFile: 260617_CasaDFL_Estrutura_Terreno.ifc; ConstructionBasis: DESIGN_ASSUMPTION; Note: Concept gabion envelope; mesh gauge, foundation, filter and retaining capacity to design.
Pset_CasaBoundary - BaseSurveyLevel_m: 14; TopSurveyLevel_m: 14.7; Status: CONCEPT_NOT_SIZED

# IfcWall: Limite north · gabião 9 · núcleo de pedra
In: Lares · Rua das Mercês · artigo 4771
PredefinedType: USERDEFINED; Material: Gabião · enchimento
Pset_CasaProvenance - DesignSource: Casa Sobreposta / configuration.json; ReferenceFile: 260617_CasaDFL_Estrutura_Terreno.ifc; ConstructionBasis: DESIGN_ASSUMPTION; Note: Concept gabion envelope; mesh gauge, foundation, filter and retaining capacity to design.
Pset_CasaBoundary - BaseSurveyLevel_m: 14; TopSurveyLevel_m: 14.8; Status: CONCEPT_NOT_SIZED

# IfcWall: Limite south · gabião 1 · núcleo de pedra
In: Lares · Rua das Mercês · artigo 4771
PredefinedType: USERDEFINED; Material: Gabião · enchimento
Pset_CasaProvenance - DesignSource: Casa Sobreposta / configuration.json; ReferenceFile: 260617_CasaDFL_Estrutura_Terreno.ifc; ConstructionBasis: DESIGN_ASSUMPTION; Note: Concept gabion envelope; mesh gauge, foundation, filter and retaining capacity to design.
Pset_CasaBoundary - BaseSurveyLevel_m: 10.25; TopSurveyLevel_m: 11.2; Status: CONCEPT_NOT_SIZED

# IfcWall: Limite south · gabião 10 · núcleo de pedra
In: Lares · Rua das Mercês · artigo 4771
PredefinedType: USERDEFINED; Material: Gabião · enchimento
Pset_CasaProvenance - DesignSource: Casa Sobreposta / configuration.json; ReferenceFile: 260617_CasaDFL_Estrutura_Terreno.ifc; ConstructionBasis: DESIGN_ASSUMPTION; Note: Concept gabion envelope; mesh gauge, foundation, filter and retaining capacity to design.
Pset_CasaBoundary - BaseSurveyLevel_m: 11.5; TopSurveyLevel_m: 12.6; Status: CONCEPT_NOT_SIZED

# IfcWall: Limite south · gabião 11 · núcleo de pedra
In: Lares · Rua das Mercês · artigo 4771
PredefinedType: USERDEFINED; Material: Gabião · enchimento
Pset_CasaProvenance - DesignSource: Casa Sobreposta / configuration.json; ReferenceFile: 260617_CasaDFL_Estrutura_Terreno.ifc; ConstructionBasis: DESIGN_ASSUMPTION; Note: Concept gabion envelope; mesh gauge, foundation, filter and retaining capacity to design.
Pset_CasaBoundary - BaseSurveyLevel_m: 11.75; TopSurveyLevel_m: 12.8; Status: CONCEPT_NOT_SIZED

# IfcWall: Limite south · gabião 12 · núcleo de pedra
In: Lares · Rua das Mercês · artigo 4771
PredefinedType: USERDEFINED; Material: Gabião · enchimento
Pset_CasaProvenance - DesignSource: Casa Sobreposta / configuration.json; ReferenceFile: 260617_CasaDFL_Estrutura_Terreno.ifc; ConstructionBasis: DESIGN_ASSUMPTION; Note: Concept gabion envelope; mesh gauge, foundation, filter and retaining capacity to design.
Pset_CasaBoundary - BaseSurveyLevel_m: 11.75; TopSurveyLevel_m: 12.8; Status: CONCEPT_NOT_SIZED

# IfcWall: Limite south · gabião 13 · núcleo de pedra
In: Lares · Rua das Mercês · artigo 4771
PredefinedType: USERDEFINED; Material: Gabião · enchimento
Pset_CasaProvenance - DesignSource: Casa Sobreposta / configuration.json; ReferenceFile: 260617_CasaDFL_Estrutura_Terreno.ifc; ConstructionBasis: DESIGN_ASSUMPTION; Note: Concept gabion envelope; mesh gauge, foundation, filter and retaining capacity to design.
Pset_CasaBoundary - BaseSurveyLevel_m: 12; TopSurveyLevel_m: 13; Status: CONCEPT_NOT_SIZED

# IfcWall: Limite south · gabião 14 · núcleo de pedra
In: Lares · Rua das Mercês · artigo 4771
PredefinedType: USERDEFINED; Material: Gabião · enchimento
Pset_CasaProvenance - DesignSource: Casa Sobreposta / configuration.json; ReferenceFile: 260617_CasaDFL_Estrutura_Terreno.ifc; ConstructionBasis: DESIGN_ASSUMPTION; Note: Concept gabion envelope; mesh gauge, foundation, filter and retaining capacity to design.
Pset_CasaBoundary - BaseSurveyLevel_m: 12; TopSurveyLevel_m: 13.1; Status: CONCEPT_NOT_SIZED

# IfcWall: Limite south · gabião 15 · núcleo de pedra
In: Lares · Rua das Mercês · artigo 4771
PredefinedType: USERDEFINED; Material: Gabião · enchimento
Pset_CasaProvenance - DesignSource: Casa Sobreposta / configuration.json; ReferenceFile: 260617_CasaDFL_Estrutura_Terreno.ifc; ConstructionBasis: DESIGN_ASSUMPTION; Note: Concept gabion envelope; mesh gauge, foundation, filter and retaining capacity to design.
Pset_CasaBoundary - BaseSurveyLevel_m: 12.25; TopSurveyLevel_m: 13.3; Status: CONCEPT_NOT_SIZED

# IfcWall: Limite south · gabião 16 · núcleo de pedra
In: Lares · Rua das Mercês · artigo 4771
PredefinedType: USERDEFINED; Material: Gabião · enchimento
Pset_CasaProvenance - DesignSource: Casa Sobreposta / configuration.json; ReferenceFile: 260617_CasaDFL_Estrutura_Terreno.ifc; ConstructionBasis: DESIGN_ASSUMPTION; Note: Concept gabion envelope; mesh gauge, foundation, filter and retaining capacity to design.
Pset_CasaBoundary - BaseSurveyLevel_m: 12.25; TopSurveyLevel_m: 13.3; Status: CONCEPT_NOT_SIZED

# IfcWall: Limite south · gabião 17 · núcleo de pedra
In: Lares · Rua das Mercês · artigo 4771
PredefinedType: USERDEFINED; Material: Gabião · enchimento
Pset_CasaProvenance - DesignSource: Casa Sobreposta / configuration.json; ReferenceFile: 260617_CasaDFL_Estrutura_Terreno.ifc; ConstructionBasis: DESIGN_ASSUMPTION; Note: Concept gabion envelope; mesh gauge, foundation, filter and retaining capacity to design.
Pset_CasaBoundary - BaseSurveyLevel_m: 12.5; TopSurveyLevel_m: 13.4; Status: CONCEPT_NOT_SIZED

# IfcWall: Limite south · gabião 18 · núcleo de pedra
In: Lares · Rua das Mercês · artigo 4771
PredefinedType: USERDEFINED; Material: Gabião · enchimento
Pset_CasaProvenance - DesignSource: Casa Sobreposta / configuration.json; ReferenceFile: 260617_CasaDFL_Estrutura_Terreno.ifc; ConstructionBasis: DESIGN_ASSUMPTION; Note: Concept gabion envelope; mesh gauge, foundation, filter and retaining capacity to design.
Pset_CasaBoundary - BaseSurveyLevel_m: 12.5; TopSurveyLevel_m: 13.6; Status: CONCEPT_NOT_SIZED

# IfcWall: Limite south · gabião 19 · núcleo de pedra
In: Lares · Rua das Mercês · artigo 4771
PredefinedType: USERDEFINED; Material: Gabião · enchimento
Pset_CasaProvenance - DesignSource: Casa Sobreposta / configuration.json; ReferenceFile: 260617_CasaDFL_Estrutura_Terreno.ifc; ConstructionBasis: DESIGN_ASSUMPTION; Note: Concept gabion envelope; mesh gauge, foundation, filter and retaining capacity to design.
Pset_CasaBoundary - BaseSurveyLevel_m: 12.75; TopSurveyLevel_m: 13.7; Status: CONCEPT_NOT_SIZED

# IfcWall: Limite south · gabião 2 · núcleo de pedra
In: Lares · Rua das Mercês · artigo 4771
PredefinedType: USERDEFINED; Material: Gabião · enchimento
Pset_CasaProvenance - DesignSource: Casa Sobreposta / configuration.json; ReferenceFile: 260617_CasaDFL_Estrutura_Terreno.ifc; ConstructionBasis: DESIGN_ASSUMPTION; Note: Concept gabion envelope; mesh gauge, foundation, filter and retaining capacity to design.
Pset_CasaBoundary - BaseSurveyLevel_m: 10.25; TopSurveyLevel_m: 11.3; Status: CONCEPT_NOT_SIZED

# IfcWall: Limite south · gabião 20 · núcleo de pedra
In: Lares · Rua das Mercês · artigo 4771
PredefinedType: USERDEFINED; Material: Gabião · enchimento
Pset_CasaProvenance - DesignSource: Casa Sobreposta / configuration.json; ReferenceFile: 260617_CasaDFL_Estrutura_Terreno.ifc; ConstructionBasis: DESIGN_ASSUMPTION; Note: Concept gabion envelope; mesh gauge, foundation, filter and retaining capacity to design.
Pset_CasaBoundary - BaseSurveyLevel_m: 12.75; TopSurveyLevel_m: 13.8; Status: CONCEPT_NOT_SIZED

# IfcWall: Limite south · gabião 21 · núcleo de pedra
In: Lares · Rua das Mercês · artigo 4771
PredefinedType: USERDEFINED; Material: Gabião · enchimento
Pset_CasaProvenance - DesignSource: Casa Sobreposta / configuration.json; ReferenceFile: 260617_CasaDFL_Estrutura_Terreno.ifc; ConstructionBasis: DESIGN_ASSUMPTION; Note: Concept gabion envelope; mesh gauge, foundation, filter and retaining capacity to design.
Pset_CasaBoundary - BaseSurveyLevel_m: 12.75; TopSurveyLevel_m: 13.9; Status: CONCEPT_NOT_SIZED

# IfcWall: Limite south · gabião 22 · núcleo de pedra
In: Lares · Rua das Mercês · artigo 4771
PredefinedType: USERDEFINED; Material: Gabião · enchimento
Pset_CasaProvenance - DesignSource: Casa Sobreposta / configuration.json; ReferenceFile: 260617_CasaDFL_Estrutura_Terreno.ifc; ConstructionBasis: DESIGN_ASSUMPTION; Note: Concept gabion envelope; mesh gauge, foundation, filter and retaining capacity to design.
Pset_CasaBoundary - BaseSurveyLevel_m: 13; TopSurveyLevel_m: 14.1; Status: CONCEPT_NOT_SIZED

# IfcWall: Limite south · gabião 23 · núcleo de pedra
In: Lares · Rua das Mercês · artigo 4771
PredefinedType: USERDEFINED; Material: Gabião · enchimento
Pset_CasaProvenance - DesignSource: Casa Sobreposta / configuration.json; ReferenceFile: 260617_CasaDFL_Estrutura_Terreno.ifc; ConstructionBasis: DESIGN_ASSUMPTION; Note: Concept gabion envelope; mesh gauge, foundation, filter and retaining capacity to design.
Pset_CasaBoundary - BaseSurveyLevel_m: 13.25; TopSurveyLevel_m: 14.3; Status: CONCEPT_NOT_SIZED

# IfcWall: Limite south · gabião 24 · núcleo de pedra
In: Lares · Rua das Mercês · artigo 4771
PredefinedType: USERDEFINED; Material: Gabião · enchimento
Pset_CasaProvenance - DesignSource: Casa Sobreposta / configuration.json; ReferenceFile: 260617_CasaDFL_Estrutura_Terreno.ifc; ConstructionBasis: DESIGN_ASSUMPTION; Note: Concept gabion envelope; mesh gauge, foundation, filter and retaining capacity to design.
Pset_CasaBoundary - BaseSurveyLevel_m: 13.25; TopSurveyLevel_m: 14.4; Status: CONCEPT_NOT_SIZED

# IfcWall: Limite south · gabião 25 · núcleo de pedra
In: Lares · Rua das Mercês · artigo 4771
PredefinedType: USERDEFINED; Material: Gabião · enchimento
Pset_CasaProvenance - DesignSource: Casa Sobreposta / configuration.json; ReferenceFile: 260617_CasaDFL_Estrutura_Terreno.ifc; ConstructionBasis: DESIGN_ASSUMPTION; Note: Concept gabion envelope; mesh gauge, foundation, filter and retaining capacity to design.
Pset_CasaBoundary - BaseSurveyLevel_m: 13.5; TopSurveyLevel_m: 14.6; Status: CONCEPT_NOT_SIZED

# IfcWall: Limite south · gabião 26 · núcleo de pedra
In: Lares · Rua das Mercês · artigo 4771
PredefinedType: USERDEFINED; Material: Gabião · enchimento
Pset_CasaProvenance - DesignSource: Casa Sobreposta / configuration.json; ReferenceFile: 260617_CasaDFL_Estrutura_Terreno.ifc; ConstructionBasis: DESIGN_ASSUMPTION; Note: Concept gabion envelope; mesh gauge, foundation, filter and retaining capacity to design.
Pset_CasaBoundary - BaseSurveyLevel_m: 13.75; TopSurveyLevel_m: 14.8; Status: CONCEPT_NOT_SIZED

# IfcWall: Limite south · gabião 27 · núcleo de pedra
In: Lares · Rua das Mercês · artigo 4771
PredefinedType: USERDEFINED; Material: Gabião · enchimento
Pset_CasaProvenance - DesignSource: Casa Sobreposta / configuration.json; ReferenceFile: 260617_CasaDFL_Estrutura_Terreno.ifc; ConstructionBasis: DESIGN_ASSUMPTION; Note: Concept gabion envelope; mesh gauge, foundation, filter and retaining capacity to design.
Pset_CasaBoundary - BaseSurveyLevel_m: 14; TopSurveyLevel_m: 15; Status: CONCEPT_NOT_SIZED

# IfcWall: Limite south · gabião 28 · núcleo de pedra
In: Lares · Rua das Mercês · artigo 4771
PredefinedType: USERDEFINED; Material: Gabião · enchimento
Pset_CasaProvenance - DesignSource: Casa Sobreposta / configuration.json; ReferenceFile: 260617_CasaDFL_Estrutura_Terreno.ifc; ConstructionBasis: DESIGN_ASSUMPTION; Note: Concept gabion envelope; mesh gauge, foundation, filter and retaining capacity to design.
Pset_CasaBoundary - BaseSurveyLevel_m: 14; TopSurveyLevel_m: 15.2; Status: CONCEPT_NOT_SIZED

# IfcWall: Limite south · gabião 29 · núcleo de pedra
In: Lares · Rua das Mercês · artigo 4771
PredefinedType: USERDEFINED; Material: Gabião · enchimento
Pset_CasaProvenance - DesignSource: Casa Sobreposta / configuration.json; ReferenceFile: 260617_CasaDFL_Estrutura_Terreno.ifc; ConstructionBasis: DESIGN_ASSUMPTION; Note: Concept gabion envelope; mesh gauge, foundation, filter and retaining capacity to design.
Pset_CasaBoundary - BaseSurveyLevel_m: 14.25; TopSurveyLevel_m: 15.4; Status: CONCEPT_NOT_SIZED

# IfcWall: Limite south · gabião 3 · núcleo de pedra
In: Lares · Rua das Mercês · artigo 4771
PredefinedType: USERDEFINED; Material: Gabião · enchimento
Pset_CasaProvenance - DesignSource: Casa Sobreposta / configuration.json; ReferenceFile: 260617_CasaDFL_Estrutura_Terreno.ifc; ConstructionBasis: DESIGN_ASSUMPTION; Note: Concept gabion envelope; mesh gauge, foundation, filter and retaining capacity to design.
Pset_CasaBoundary - BaseSurveyLevel_m: 10.25; TopSurveyLevel_m: 11.6; Status: CONCEPT_NOT_SIZED

# IfcWall: Limite south · gabião 30 · núcleo de pedra
In: Lares · Rua das Mercês · artigo 4771
PredefinedType: USERDEFINED; Material: Gabião · enchimento
Pset_CasaProvenance - DesignSource: Casa Sobreposta / configuration.json; ReferenceFile: 260617_CasaDFL_Estrutura_Terreno.ifc; ConstructionBasis: DESIGN_ASSUMPTION; Note: Concept gabion envelope; mesh gauge, foundation, filter and retaining capacity to design.
Pset_CasaBoundary - BaseSurveyLevel_m: 14.5; TopSurveyLevel_m: 15.6; Status: CONCEPT_NOT_SIZED

# IfcWall: Limite south · gabião 31 · núcleo de pedra
In: Lares · Rua das Mercês · artigo 4771
PredefinedType: USERDEFINED; Material: Gabião · enchimento
Pset_CasaProvenance - DesignSource: Casa Sobreposta / configuration.json; ReferenceFile: 260617_CasaDFL_Estrutura_Terreno.ifc; ConstructionBasis: DESIGN_ASSUMPTION; Note: Concept gabion envelope; mesh gauge, foundation, filter and retaining capacity to design.
Pset_CasaBoundary - BaseSurveyLevel_m: 14.75; TopSurveyLevel_m: 15.8; Status: CONCEPT_NOT_SIZED

# IfcWall: Limite south · gabião 4 · núcleo de pedra
In: Lares · Rua das Mercês · artigo 4771
PredefinedType: USERDEFINED; Material: Gabião · enchimento
Pset_CasaProvenance - DesignSource: Casa Sobreposta / configuration.json; ReferenceFile: 260617_CasaDFL_Estrutura_Terreno.ifc; ConstructionBasis: DESIGN_ASSUMPTION; Note: Concept gabion envelope; mesh gauge, foundation, filter and retaining capacity to design.
Pset_CasaBoundary - BaseSurveyLevel_m: 10.75; TopSurveyLevel_m: 11.9; Status: CONCEPT_NOT_SIZED

# IfcWall: Limite south · gabião 5 · núcleo de pedra
In: Lares · Rua das Mercês · artigo 4771
PredefinedType: USERDEFINED; Material: Gabião · enchimento
Pset_CasaProvenance - DesignSource: Casa Sobreposta / configuration.json; ReferenceFile: 260617_CasaDFL_Estrutura_Terreno.ifc; ConstructionBasis: DESIGN_ASSUMPTION; Note: Concept gabion envelope; mesh gauge, foundation, filter and retaining capacity to design.
Pset_CasaBoundary - BaseSurveyLevel_m: 11; TopSurveyLevel_m: 12; Status: CONCEPT_NOT_SIZED

# IfcWall: Limite south · gabião 6 · núcleo de pedra
In: Lares · Rua das Mercês · artigo 4771
PredefinedType: USERDEFINED; Material: Gabião · enchimento
Pset_CasaProvenance - DesignSource: Casa Sobreposta / configuration.json; ReferenceFile: 260617_CasaDFL_Estrutura_Terreno.ifc; ConstructionBasis: DESIGN_ASSUMPTION; Note: Concept gabion envelope; mesh gauge, foundation, filter and retaining capacity to design.
Pset_CasaBoundary - BaseSurveyLevel_m: 11; TopSurveyLevel_m: 12.1; Status: CONCEPT_NOT_SIZED

# IfcWall: Limite south · gabião 7 · núcleo de pedra
In: Lares · Rua das Mercês · artigo 4771
PredefinedType: USERDEFINED; Material: Gabião · enchimento
Pset_CasaProvenance - DesignSource: Casa Sobreposta / configuration.json; ReferenceFile: 260617_CasaDFL_Estrutura_Terreno.ifc; ConstructionBasis: DESIGN_ASSUMPTION; Note: Concept gabion envelope; mesh gauge, foundation, filter and retaining capacity to design.
Pset_CasaBoundary - BaseSurveyLevel_m: 11.25; TopSurveyLevel_m: 12.2; Status: CONCEPT_NOT_SIZED

# IfcWall: Limite south · gabião 8 · núcleo de pedra
In: Lares · Rua das Mercês · artigo 4771
PredefinedType: USERDEFINED; Material: Gabião · enchimento
Pset_CasaProvenance - DesignSource: Casa Sobreposta / configuration.json; ReferenceFile: 260617_CasaDFL_Estrutura_Terreno.ifc; ConstructionBasis: DESIGN_ASSUMPTION; Note: Concept gabion envelope; mesh gauge, foundation, filter and retaining capacity to design.
Pset_CasaBoundary - BaseSurveyLevel_m: 11.25; TopSurveyLevel_m: 12.4; Status: CONCEPT_NOT_SIZED

# IfcWall: Limite south · gabião 9 · núcleo de pedra
In: Lares · Rua das Mercês · artigo 4771
PredefinedType: USERDEFINED; Material: Gabião · enchimento
Pset_CasaProvenance - DesignSource: Casa Sobreposta / configuration.json; ReferenceFile: 260617_CasaDFL_Estrutura_Terreno.ifc; ConstructionBasis: DESIGN_ASSUMPTION; Note: Concept gabion envelope; mesh gauge, foundation, filter and retaining capacity to design.
Pset_CasaBoundary - BaseSurveyLevel_m: 11.5; TopSurveyLevel_m: 12.5; Status: CONCEPT_NOT_SIZED

# IfcWall: Pódio · bordo junto à cisterna (3)
In: 00 · Habitação e estacionamento
PredefinedType: USERDEFINED; Material: Betão armado / Stahlbeton
Pset_CasaProvenance - DesignSource: Casa Sobreposta / configuration.json; ReferenceFile: 260617_CasaDFL_Estrutura_Terreno.ifc; ConstructionBasis: DESIGN_ASSUMPTION

# IfcWall: Pódio · contenção norte (16)
In: 00 · Habitação e estacionamento
PredefinedType: USERDEFINED; Material: Betão armado / Stahlbeton
Pset_CasaProvenance - DesignSource: Casa Sobreposta / configuration.json; ReferenceFile: 260617_CasaDFL_Estrutura_Terreno.ifc; ConstructionBasis: DESIGN_ASSUMPTION

# IfcWall: Pódio · contenção sul (16)
In: 00 · Habitação e estacionamento
PredefinedType: USERDEFINED; Material: Betão armado / Stahlbeton
Pset_CasaProvenance - DesignSource: Casa Sobreposta / configuration.json; ReferenceFile: 260617_CasaDFL_Estrutura_Terreno.ifc; ConstructionBasis: DESIGN_ASSUMPTION

# IfcWindow (10)
In: 00 · Habitação e estacionamento
PredefinedType: WINDOW; PartitioningType: SINGLE_PANEL; Material: Vidro / Normalglas
Pset_CasaProvenance - DesignSource: Casa Sobreposta / configuration.json; ReferenceFile: 260617_CasaDFL_Estrutura_Terreno.ifc; ConstructionBasis: DESIGN_ASSUMPTION
Name | OverallHeight (m) | OverallWidth (m)
Rasgo norte 1 | 0.3 | 3.79
Rasgo norte 2 | 0.3 | 3.79
Rasgo norte 3 | 0.3 | 3.79
Rasgo norte 4 | 0.3 | 3.79
Rasgo norte 5 | 0.3 | 3.79
Rasgo norte 6 | 0.3 | 3.79
Rasgo norte 7 | 0.3 | 0.71
Fachada poente integralmente envidraçada · módulo 1 | 3 | 1.55 | Pset_CasaGlazedFacade - Revision: R02 · kiwi pergola; Facade: WEST / highlighted end in user sketch; Infill: Full-height glazing; no opaque infill; GlazingSpecification: 8 mm nominal representation only; insulated safety glazing assembly to specify
Fachada poente integralmente envidraçada · módulo 2 | 3 | 1.55 | Pset_CasaGlazedFacade - Revision: R02 · kiwi pergola; Facade: WEST / highlighted end in user sketch; Infill: Full-height glazing; no opaque infill; GlazingSpecification: 8 mm nominal representation only; insulated safety glazing assembly to specify
Fachada poente integralmente envidraçada · módulo 3 | 3 | 1.55 | Pset_CasaGlazedFacade - Revision: R02 · kiwi pergola; Facade: WEST / highlighted end in user sketch; Infill: Full-height glazing; no opaque infill; GlazingSpecification: 8 mm nominal representation only; insulated safety glazing assembly to specify
